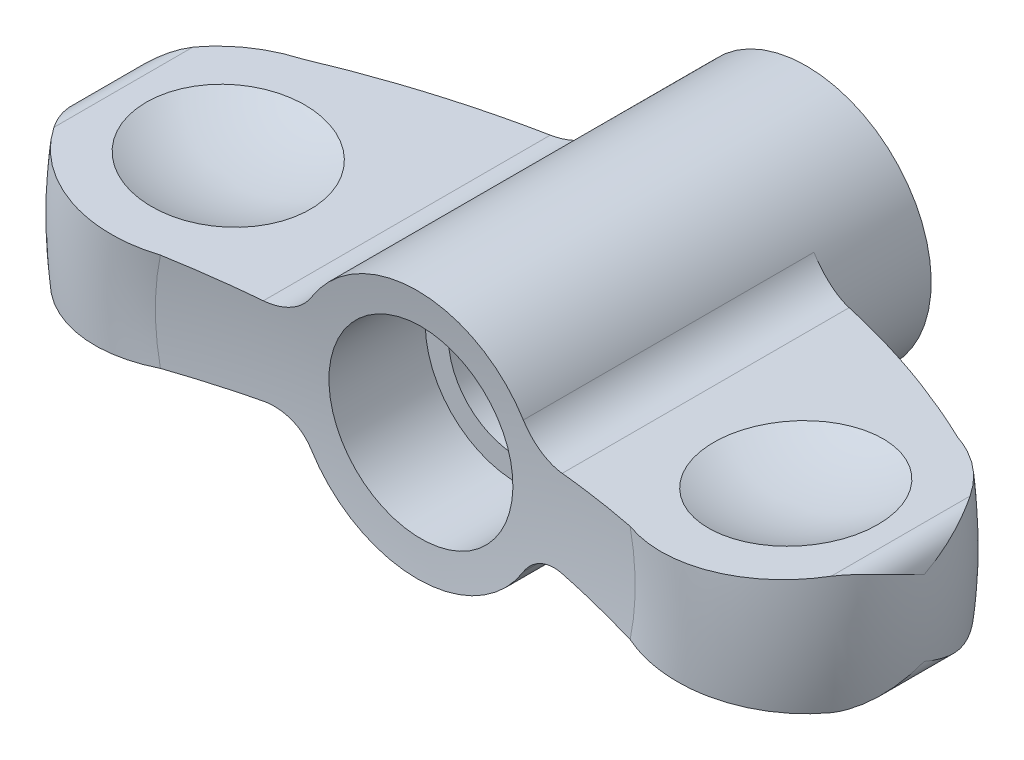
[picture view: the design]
ISO-10303-21;
HEADER;
FILE_DESCRIPTION(('STEP AP214'),'2;1');
FILE_NAME('part.step','',(''),(''),'','','');
FILE_SCHEMA(('AUTOMOTIVE_DESIGN { 1 0 10303 214 1 1 1 1 }'));
ENDSEC;
DATA;
#1=APPLICATION_CONTEXT('core data for automotive mechanical design processes');
#2=APPLICATION_PROTOCOL_DEFINITION('international standard','automotive_design',2000,#1);
#3=PRODUCT_CONTEXT('',#1,'mechanical');
#4=PRODUCT('Part','Part','',(#3));
#5=PRODUCT_RELATED_PRODUCT_CATEGORY('part','',(#4));
#6=PRODUCT_DEFINITION_FORMATION('','',#4);
#7=PRODUCT_DEFINITION_CONTEXT('part definition',#1,'design');
#8=PRODUCT_DEFINITION('design','',#6,#7);
#9=PRODUCT_DEFINITION_SHAPE('','',#8);
#10=(LENGTH_UNIT() NAMED_UNIT(*) SI_UNIT(.MILLI.,.METRE.));
#11=(NAMED_UNIT(*) PLANE_ANGLE_UNIT() SI_UNIT($,.RADIAN.));
#12=(NAMED_UNIT(*) SI_UNIT($,.STERADIAN.) SOLID_ANGLE_UNIT());
#13=UNCERTAINTY_MEASURE_WITH_UNIT(LENGTH_MEASURE(1.E-05),#10,'distance_accuracy_value','');
#14=(GEOMETRIC_REPRESENTATION_CONTEXT(3) GLOBAL_UNCERTAINTY_ASSIGNED_CONTEXT((#13)) GLOBAL_UNIT_ASSIGNED_CONTEXT((#10,
#11,#12)) REPRESENTATION_CONTEXT('',''));
#15=CARTESIAN_POINT('',(0.,0.,0.));
#16=DIRECTION('',(0.,0.,1.));
#17=DIRECTION('',(1.,0.,0.));
#18=AXIS2_PLACEMENT_3D('',#15,#16,#17);
#19=CARTESIAN_POINT('',(0.,0.,22.4));
#20=DIRECTION('',(0.,0.,1.));
#21=DIRECTION('',(-1.09310760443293E-09,1.,0.));
#22=AXIS2_PLACEMENT_3D('',#19,#20,#21);
#23=TOROIDAL_SURFACE('',#22,21.8999999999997,9.6);
#24=CARTESIAN_POINT('',(-18.1474454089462,-3.75149992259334,13.4105144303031));
#25=CARTESIAN_POINT('',(-17.8905850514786,-3.73467864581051,13.5060281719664));
#26=CARTESIAN_POINT('',(-17.637760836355,-3.71812168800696,13.6124268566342));
#27=CARTESIAN_POINT('',(-17.1419285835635,-3.68565061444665,13.8461211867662));
#28=CARTESIAN_POINT('',(-16.8989202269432,-3.66973647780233,13.9734161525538));
#29=CARTESIAN_POINT('',(-16.424509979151,-3.63866828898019,14.2479997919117));
#30=CARTESIAN_POINT('',(-16.1931050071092,-3.62351403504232,14.3952831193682));
#31=CARTESIAN_POINT('',(-15.7434802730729,-3.59406900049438,14.7088327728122));
#32=CARTESIAN_POINT('',(-15.5252603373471,-3.579778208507,14.8750988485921));
#33=CARTESIAN_POINT('',(-15.1034606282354,-3.55215537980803,15.2255617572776));
#34=CARTESIAN_POINT('',(-14.8998888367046,-3.53882386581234,15.409768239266));
#35=CARTESIAN_POINT('',(-14.5090032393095,-3.51322554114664,15.7947666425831));
#36=CARTESIAN_POINT('',(-14.3216896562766,-3.50095874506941,15.995558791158));
#37=CARTESIAN_POINT('',(-13.964772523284,-3.47758494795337,16.4122828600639));
#38=CARTESIAN_POINT('',(-13.7951642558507,-3.46647763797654,16.6282107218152));
#39=CARTESIAN_POINT('',(-13.4749045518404,-3.44550446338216,17.0737519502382));
#40=CARTESIAN_POINT('',(-13.3242529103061,-3.43563858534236,17.3033651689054));
#41=CARTESIAN_POINT('',(-13.0439598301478,-3.41728274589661,17.7732237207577));
#42=CARTESIAN_POINT('',(-12.9141954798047,-3.40878473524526,18.0133954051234));
#43=CARTESIAN_POINT('',(-12.6756273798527,-3.39316138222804,18.5039680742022));
#44=CARTESIAN_POINT('',(-12.5668227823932,-3.3860359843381,18.754368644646));
#45=CARTESIAN_POINT('',(-12.3710778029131,-3.37321703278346,19.2636307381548));
#46=CARTESIAN_POINT('',(-12.284138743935,-3.36752356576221,19.5224927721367));
#47=CARTESIAN_POINT('',(-12.1328924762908,-3.35761874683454,20.0467739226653));
#48=CARTESIAN_POINT('',(-12.06858489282,-3.35340737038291,20.3121929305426));
#49=CARTESIAN_POINT('',(-11.9641647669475,-3.34656910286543,20.8426066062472));
#50=CARTESIAN_POINT('',(-11.9236219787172,-3.34391403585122,21.1075162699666));
#51=CARTESIAN_POINT('',(-11.8652424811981,-3.34009087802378,21.639835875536));
#52=CARTESIAN_POINT('',(-11.8474054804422,-3.33892276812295,21.9072457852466));
#53=CARTESIAN_POINT('',(-11.8345982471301,-3.33808404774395,22.4425774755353));
#54=CARTESIAN_POINT('',(-11.8396248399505,-3.33841322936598,22.7104991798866));
#55=CARTESIAN_POINT('',(-11.8724923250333,-3.34056565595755,23.2449323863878));
#56=CARTESIAN_POINT('',(-11.9003330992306,-3.34238889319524,23.5114438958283));
#57=CARTESIAN_POINT('',(-11.9780680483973,-3.34747960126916,24.0376567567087));
#58=CARTESIAN_POINT('',(-12.027669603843,-3.35072790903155,24.2974015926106));
#59=CARTESIAN_POINT('',(-12.1484267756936,-3.35863605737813,24.8118052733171));
#60=CARTESIAN_POINT('',(-12.2195821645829,-3.36329588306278,25.0664641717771));
#61=CARTESIAN_POINT('',(-12.382844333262,-3.37398759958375,25.5689078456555));
#62=CARTESIAN_POINT('',(-12.4749485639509,-3.38001932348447,25.8166934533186));
#63=CARTESIAN_POINT('',(-12.6794078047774,-3.3934089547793,26.3038316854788));
#64=CARTESIAN_POINT('',(-12.7917703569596,-3.40076735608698,26.5431811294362));
#65=CARTESIAN_POINT('',(-13.0369078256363,-3.41682092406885,27.0137884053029));
#66=CARTESIAN_POINT('',(-13.1698514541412,-3.42552713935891,27.2449579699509));
#67=CARTESIAN_POINT('',(-13.4544154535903,-3.44416267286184,27.69545672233));
#68=CARTESIAN_POINT('',(-13.6060365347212,-3.45409203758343,27.914785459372));
#69=CARTESIAN_POINT('',(-13.9268367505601,-3.47510060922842,28.3401572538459));
#70=CARTESIAN_POINT('',(-14.0960166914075,-3.4861798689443,28.5461997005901));
#71=CARTESIAN_POINT('',(-14.4507138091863,-3.50940828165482,28.9436423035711));
#72=CARTESIAN_POINT('',(-14.6362312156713,-3.52155744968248,29.1350422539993));
#73=CARTESIAN_POINT('',(-15.0260268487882,-3.54708439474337,29.5054914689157));
#74=CARTESIAN_POINT('',(-15.2305978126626,-3.56048134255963,29.6842314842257));
#75=CARTESIAN_POINT('',(-15.6538967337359,-3.58820235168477,30.0239900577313));
#76=CARTESIAN_POINT('',(-15.8726245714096,-3.60252640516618,30.1850087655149));
#77=CARTESIAN_POINT('',(-16.3227525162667,-3.6320043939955,30.4882695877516));
#78=CARTESIAN_POINT('',(-16.5541555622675,-3.64715852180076,30.6305073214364));
#79=CARTESIAN_POINT('',(-17.0278914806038,-3.67818255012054,30.8951425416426));
#80=CARTESIAN_POINT('',(-17.2702206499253,-3.69405220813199,31.017546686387));
#81=CARTESIAN_POINT('',(-17.7669669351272,-3.72658313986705,31.2429802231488));
#82=CARTESIAN_POINT('',(-18.0214889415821,-3.74325128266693,31.3457775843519));
#83=CARTESIAN_POINT('',(-18.5382654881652,-3.77709395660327,31.5295393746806));
#84=CARTESIAN_POINT('',(-18.8005200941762,-3.79426849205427,31.6105036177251));
#85=CARTESIAN_POINT('',(-19.3309113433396,-3.82900276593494,31.7500060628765));
#86=CARTESIAN_POINT('',(-19.5990481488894,-3.8465625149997,31.8085436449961));
#87=CARTESIAN_POINT('',(-20.1392890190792,-3.88194182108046,31.9027453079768));
#88=CARTESIAN_POINT('',(-20.411393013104,-3.899761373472,31.9384097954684));
#89=CARTESIAN_POINT('',(-20.9576381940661,-3.93553388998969,31.9865808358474));
#90=CARTESIAN_POINT('',(-21.2317794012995,-3.95348685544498,31.9990871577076));
#91=CARTESIAN_POINT('',(-21.7801364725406,-3.98939767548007,32.0008164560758));
#92=CARTESIAN_POINT('',(-22.0543523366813,-4.00735553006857,31.9900393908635));
#93=CARTESIAN_POINT('',(-22.6008596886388,-4.04314521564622,31.9452447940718));
#94=CARTESIAN_POINT('',(-22.8731513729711,-4.06097705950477,31.9112296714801));
#95=CARTESIAN_POINT('',(-23.4138724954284,-4.09638781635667,31.8201695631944));
#96=CARTESIAN_POINT('',(-23.6823019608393,-4.11396673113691,31.7631247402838));
#97=CARTESIAN_POINT('',(-24.2118784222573,-4.14864764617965,31.6267614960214));
#98=CARTESIAN_POINT('',(-24.4730575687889,-4.16575175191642,31.5475684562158));
#99=CARTESIAN_POINT('',(-24.9877954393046,-4.19946091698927,31.3673123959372));
#100=CARTESIAN_POINT('',(-25.2413540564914,-4.21606596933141,31.2662490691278));
#101=CARTESIAN_POINT('',(-25.7391278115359,-4.2486641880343,31.0428965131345));
#102=CARTESIAN_POINT('',(-25.983338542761,-4.26465706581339,30.9205974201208));
#103=CARTESIAN_POINT('',(-26.4605066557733,-4.29590586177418,30.6556646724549));
#104=CARTESIAN_POINT('',(-26.6934645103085,-4.31116181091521,30.5130318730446));
#105=CARTESIAN_POINT('',(-27.1452633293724,-4.34074922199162,30.2092249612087));
#106=CARTESIAN_POINT('',(-27.3641711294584,-4.35508506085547,30.0481506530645));
#107=CARTESIAN_POINT('',(-27.7875858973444,-4.38281365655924,29.708008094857));
#108=CARTESIAN_POINT('',(-27.9920934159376,-4.39620644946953,29.5289405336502));
#109=CARTESIAN_POINT('',(-28.3848624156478,-4.42192811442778,29.1544313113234));
#110=CARTESIAN_POINT('',(-28.5731528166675,-4.43425888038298,28.9590200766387));
#111=CARTESIAN_POINT('',(-28.9324617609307,-4.45778931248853,28.5530043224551));
#112=CARTESIAN_POINT('',(-29.1034908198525,-4.46898966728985,28.3424091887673));
#113=CARTESIAN_POINT('',(-29.3193740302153,-4.48312743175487,28.0522910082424));
#114=CARTESIAN_POINT('',(-29.3724491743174,-4.48660321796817,27.978811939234));
#115=CARTESIAN_POINT('',(-29.476441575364,-4.49341347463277,27.8304567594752));
#116=CARTESIAN_POINT('',(-29.5273611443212,-4.49674809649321,27.7555822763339));
#117=CARTESIAN_POINT('',(-29.5772181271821,-4.50001313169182,27.6799919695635));
#118=B_SPLINE_CURVE_WITH_KNOTS('',3,(#24,#25,#26,#27,#28,#29,#30,#31,#32,#33,#34,#35,#36,#37,
#38,#39,#40,#41,#42,#43,#44,#45,#46,#47,#48,#49,#50,#51,#52,#53,#54,#55,#56,#57,#58,#59,#60,#61,
#62,#63,#64,#65,#66,#67,#68,#69,#70,#71,#72,#73,#74,#75,#76,#77,#78,#79,#80,#81,#82,#83,#84,#85,
#86,#87,#88,#89,#90,#91,#92,#93,#94,#95,#96,#97,#98,#99,#100,#101,#102,#103,#104,#105,#106,#107,
#108,#109,#110,#111,#112,#113,#114,#115,#116,#117),.UNSPECIFIED.,.F.,.F.,(4,2,2,2,2,2,2,2,2,2,2,
2,2,2,2,2,2,2,2,2,2,2,2,2,2,2,2,2,2,2,2,2,2,2,2,2,2,2,2,2,2,2,2,2,2,2,4),(0.,0.823429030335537,
1.64683128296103,2.47001373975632,3.29318534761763,4.11680216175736,4.94043026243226,
5.76383834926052,6.5872375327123,7.40559872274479,8.22392680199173,9.04230438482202,
9.8606684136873,10.6637182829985,11.4667578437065,12.2696859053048,13.0726098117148,
13.8650526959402,14.6574872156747,15.449825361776,16.2424591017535,17.0419728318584,
17.8415169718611,18.6410978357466,19.4406899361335,20.2556974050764,21.070697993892,
21.8858883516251,22.7008044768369,23.5248358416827,24.3488742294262,25.1729353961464,
25.9969819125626,26.8210366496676,27.6450928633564,28.4690636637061,29.2930286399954,
30.1124203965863,30.9318236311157,31.7516084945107,32.5713588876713,33.3868657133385,
34.2023413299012,35.0163312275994,35.8298222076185,36.1019244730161,36.3737270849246),.UNSPECIFIED.);
#119=CARTESIAN_POINT('',(-17.8721248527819,-3.73346972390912,31.2823000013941));
#120=VERTEX_POINT('',#119);
#121=CARTESIAN_POINT('',(-29.5770181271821,-4.50000003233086,27.6802951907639));
#122=VERTEX_POINT('',#121);
#123=EDGE_CURVE('E175',#120,#122,#118,.T.);
#124=ORIENTED_EDGE('',*,*,#123,.F.);
#125=CARTESIAN_POINT('',(0.,0.,31.2823000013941));
#126=DIRECTION('',(0.,0.,1.));
#127=DIRECTION('',(-1.09310760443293E-09,1.,0.));
#128=AXIS2_PLACEMENT_3D('',#125,#126,#127);
#129=CIRCLE('',#128,18.2579200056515);
#130=CARTESIAN_POINT('',(-17.8721248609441,3.7334696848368,31.2823000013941));
#131=VERTEX_POINT('',#130);
#132=EDGE_CURVE('E187',#131,#120,#129,.T.);
#133=ORIENTED_EDGE('',*,*,#132,.F.);
#134=CARTESIAN_POINT('',(-29.5772181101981,4.50001306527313,27.6799920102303));
#135=CARTESIAN_POINT('',(-29.4283813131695,4.49026603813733,27.9057071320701));
#136=CARTESIAN_POINT('',(-29.2699701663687,4.47989200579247,28.125073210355));
#137=CARTESIAN_POINT('',(-28.9352574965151,4.4579723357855,28.5496181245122));
#138=CARTESIAN_POINT('',(-28.7589571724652,4.44642677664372,28.7547979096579));
#139=CARTESIAN_POINT('',(-28.3898682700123,4.42225587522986,29.1493363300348));
#140=CARTESIAN_POINT('',(-28.1970944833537,4.40963150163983,29.3387088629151));
#141=CARTESIAN_POINT('',(-27.7963194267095,4.38338553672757,29.700509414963));
#142=CARTESIAN_POINT('',(-27.5883182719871,4.36976395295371,29.8729375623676));
#143=CARTESIAN_POINT('',(-27.1584989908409,4.3416159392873,30.1997036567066));
#144=CARTESIAN_POINT('',(-26.9366758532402,4.32708918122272,30.3540349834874));
#145=CARTESIAN_POINT('',(-26.4808650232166,4.29723903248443,30.6434656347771));
#146=CARTESIAN_POINT('',(-26.2468771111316,4.28191562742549,30.7785646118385));
#147=CARTESIAN_POINT('',(-25.7684462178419,4.25058413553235,31.0285776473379));
#148=CARTESIAN_POINT('',(-25.5240048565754,4.23457615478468,31.1434948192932));
#149=CARTESIAN_POINT('',(-25.0263706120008,4.20198707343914,31.3523874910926));
#150=CARTESIAN_POINT('',(-24.7731777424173,4.18540597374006,31.446363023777));
#151=CARTESIAN_POINT('',(-24.2590478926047,4.1517366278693,31.612996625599));
#152=CARTESIAN_POINT('',(-23.9980896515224,4.13464698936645,31.6855888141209));
#153=CARTESIAN_POINT('',(-23.4709078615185,4.10012289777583,31.8086173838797));
#154=CARTESIAN_POINT('',(-23.2046821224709,4.08268830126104,31.8590443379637));
#155=CARTESIAN_POINT('',(-22.6689091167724,4.04760158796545,31.9373839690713));
#156=CARTESIAN_POINT('',(-22.399361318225,4.02994943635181,31.9652929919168));
#157=CARTESIAN_POINT('',(-21.858996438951,3.99456201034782,31.9984159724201));
#158=CARTESIAN_POINT('',(-21.5881799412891,3.97682677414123,32.003639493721));
#159=CARTESIAN_POINT('',(-21.0454404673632,3.94128384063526,31.9913795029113));
#160=CARTESIAN_POINT('',(-20.7735205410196,3.92347634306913,31.9737602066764));
#161=CARTESIAN_POINT('',(-20.232112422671,3.88802059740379,31.9157373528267));
#162=CARTESIAN_POINT('',(-19.9626242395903,3.87037234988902,31.8753337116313));
#163=CARTESIAN_POINT('',(-19.4280257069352,3.83536255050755,31.7720671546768));
#164=CARTESIAN_POINT('',(-19.1629144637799,3.81800094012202,31.7092088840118));
#165=CARTESIAN_POINT('',(-18.6387730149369,3.78367595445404,31.5614710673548));
#166=CARTESIAN_POINT('',(-18.3797450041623,3.76671272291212,31.4765837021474));
#167=CARTESIAN_POINT('',(-17.8682212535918,3.73321404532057,31.2848646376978));
#168=CARTESIAN_POINT('',(-17.6157711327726,3.7166815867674,31.1779106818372));
#169=CARTESIAN_POINT('',(-17.1207308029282,3.68426237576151,30.9431230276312));
#170=CARTESIAN_POINT('',(-16.878140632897,3.66837562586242,30.815289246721));
#171=CARTESIAN_POINT('',(-16.404527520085,3.63735964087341,30.5396362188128));
#172=CARTESIAN_POINT('',(-16.1735051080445,3.62223044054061,30.3918160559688));
#173=CARTESIAN_POINT('',(-15.7246795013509,3.59283774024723,30.0772205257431));
#174=CARTESIAN_POINT('',(-15.5068766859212,3.57857426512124,29.9104446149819));
#175=CARTESIAN_POINT('',(-15.0856203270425,3.55098702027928,29.5587225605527));
#176=CARTESIAN_POINT('',(-14.8821981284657,3.53766530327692,29.3737387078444));
#177=CARTESIAN_POINT('',(-14.4917116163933,3.51209311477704,28.9871837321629));
#178=CARTESIAN_POINT('',(-14.3046468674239,3.49984261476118,28.7856130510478));
#179=CARTESIAN_POINT('',(-13.948272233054,3.47650434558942,28.367276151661));
#180=CARTESIAN_POINT('',(-13.7789624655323,3.46541658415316,28.1505098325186));
#181=CARTESIAN_POINT('',(-13.4594078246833,3.44448958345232,27.7032976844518));
#182=CARTESIAN_POINT('',(-13.3091626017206,3.43465032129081,27.4728521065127));
#183=CARTESIAN_POINT('',(-13.0300075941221,3.41636901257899,27.0017206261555));
#184=CARTESIAN_POINT('',(-12.9009427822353,3.40791681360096,26.7611269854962));
#185=CARTESIAN_POINT('',(-12.6638563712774,3.39239049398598,26.2698561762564));
#186=CARTESIAN_POINT('',(-12.55582645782,3.38531582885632,26.0191830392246));
#187=CARTESIAN_POINT('',(-12.3616487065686,3.37259951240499,25.5094385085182));
#188=CARTESIAN_POINT('',(-12.2755026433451,3.36695797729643,25.2503664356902));
#189=CARTESIAN_POINT('',(-12.1258566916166,3.35715796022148,24.7257346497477));
#190=CARTESIAN_POINT('',(-12.0623564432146,3.35299945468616,24.4601750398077));
#191=CARTESIAN_POINT('',(-11.9595441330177,3.34626648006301,23.9295575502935));
#192=CARTESIAN_POINT('',(-11.9198013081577,3.34366380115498,23.6645834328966));
#193=CARTESIAN_POINT('',(-11.8630211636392,3.33994538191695,23.1322038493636));
#194=CARTESIAN_POINT('',(-11.8459835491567,3.33882962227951,22.8647984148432));
#195=CARTESIAN_POINT('',(-11.8347668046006,3.33809505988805,22.3295252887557));
#196=CARTESIAN_POINT('',(-11.8405861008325,3.33847615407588,22.0616576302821));
#197=CARTESIAN_POINT('',(-11.875027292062,3.34073163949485,21.5273997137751));
#198=CARTESIAN_POINT('',(-11.9036490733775,3.34260602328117,21.2610094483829));
#199=CARTESIAN_POINT('',(-11.9829240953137,3.3477975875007,20.7350583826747));
#200=CARTESIAN_POINT('',(-12.0332886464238,3.35109586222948,20.475453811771));
#201=CARTESIAN_POINT('',(-12.1555550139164,3.35910284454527,19.9613934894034));
#202=CARTESIAN_POINT('',(-12.2274566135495,3.36381153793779,19.7069376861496));
#203=CARTESIAN_POINT('',(-12.3921774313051,3.37459877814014,19.2049950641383));
#204=CARTESIAN_POINT('',(-12.4849912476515,3.38067697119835,18.9575064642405));
#205=CARTESIAN_POINT('',(-12.6908448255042,3.39415791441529,18.4709993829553));
#206=CARTESIAN_POINT('',(-12.8038936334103,3.40156125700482,18.2319847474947));
#207=CARTESIAN_POINT('',(-13.0503991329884,3.41770441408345,17.7620583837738));
#208=CARTESIAN_POINT('',(-13.1840279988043,3.42645550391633,17.5312373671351));
#209=CARTESIAN_POINT('',(-13.4698675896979,3.44517457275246,17.0815911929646));
#210=CARTESIAN_POINT('',(-13.6220707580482,3.4551420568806,16.8627612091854));
#211=CARTESIAN_POINT('',(-13.9440945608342,3.47623075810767,16.4382825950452));
#212=CARTESIAN_POINT('',(-14.1139279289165,3.48735280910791,16.2326436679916));
#213=CARTESIAN_POINT('',(-14.4698944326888,3.51066435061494,15.8360721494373));
#214=CARTESIAN_POINT('',(-14.6560271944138,3.52285381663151,15.6451392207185));
#215=CARTESIAN_POINT('',(-15.0471805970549,3.54846967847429,15.2755429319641));
#216=CARTESIAN_POINT('',(-15.2525053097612,3.56191598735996,15.0972026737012));
#217=CARTESIAN_POINT('',(-15.6772923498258,3.58973444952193,14.7583242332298));
#218=CARTESIAN_POINT('',(-15.8967545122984,3.60410659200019,14.5977858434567));
#219=CARTESIAN_POINT('',(-16.3478939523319,3.63365082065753,14.2958496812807));
#220=CARTESIAN_POINT('',(-16.5795509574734,3.648821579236,14.1544214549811));
#221=CARTESIAN_POINT('',(-17.0537037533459,3.67987290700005,13.8914238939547));
#222=CARTESIAN_POINT('',(-17.2961933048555,3.69575306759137,13.7698433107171));
#223=CARTESIAN_POINT('',(-17.6425873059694,3.71843772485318,13.6138611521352));
#224=CARTESIAN_POINT('',(-17.74267739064,3.7249924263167,13.5707938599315));
#225=CARTESIAN_POINT('',(-17.9441132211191,3.73818406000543,13.4880908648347));
#226=CARTESIAN_POINT('',(-18.0454572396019,3.74482087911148,13.4484509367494));
#227=CARTESIAN_POINT('',(-18.1474454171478,3.75149988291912,13.4105144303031));
#228=B_SPLINE_CURVE_WITH_KNOTS('',3,(#134,#135,#136,#137,#138,#139,#140,#141,#142,#143,#144,
#145,#146,#147,#148,#149,#150,#151,#152,#153,#154,#155,#156,#157,#158,#159,#160,#161,#162,#163,
#164,#165,#166,#167,#168,#169,#170,#171,#172,#173,#174,#175,#176,#177,#178,#179,#180,#181,#182,
#183,#184,#185,#186,#187,#188,#189,#190,#191,#192,#193,#194,#195,#196,#197,#198,#199,#200,#201,
#202,#203,#204,#205,#206,#207,#208,#209,#210,#211,#212,#213,#214,#215,#216,#217,#218,#219,#220,
#221,#222,#223,#224,#225,#226,#227),.UNSPECIFIED.,.F.,.F.,(4,2,2,2,2,2,2,2,2,2,2,2,2,2,2,2,2,2,
2,2,2,2,2,2,2,2,2,2,2,2,2,2,2,2,2,2,2,2,2,2,2,2,2,2,2,2,4),(0.,0.81138385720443,
1.62271336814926,2.43332187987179,3.24392425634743,4.05482224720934,4.86573488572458,
5.6765223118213,6.48730846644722,7.30056707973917,8.11417124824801,8.92790742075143,
9.74130050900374,10.5595508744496,11.3778042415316,12.1958884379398,13.0142634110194,
13.8373004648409,14.6603407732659,15.4834188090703,16.3065204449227,17.131364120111,
17.9561858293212,18.7810130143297,19.6058250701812,20.4243011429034,21.242453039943,
22.0606712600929,22.8788764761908,23.6817568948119,24.484626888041,25.2874416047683,
26.0902523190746,26.8827166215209,27.6751729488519,28.4674248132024,29.2600317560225,
30.0596712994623,30.8589865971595,31.6588832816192,32.458761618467,33.2746912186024,
34.0906113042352,34.905215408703,35.7193562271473,36.0467859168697,36.3738060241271),.UNSPECIFIED.);
#229=CARTESIAN_POINT('',(-29.577018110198,4.49999996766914,27.6802952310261));
#230=VERTEX_POINT('',#229);
#231=EDGE_CURVE('E289',#230,#131,#228,.T.);
#232=ORIENTED_EDGE('',*,*,#231,.F.);
#233=CARTESIAN_POINT('',(-31.3695646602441,2.86363632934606,22.4));
#234=CARTESIAN_POINT('',(-31.3693228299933,2.86628555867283,22.4059654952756));
#235=CARTESIAN_POINT('',(-31.3690751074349,2.86893434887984,22.4119311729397));
#236=CARTESIAN_POINT('',(-31.3455550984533,3.11453940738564,22.9652019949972));
#237=CARTESIAN_POINT('',(-31.2727100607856,3.35362318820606,23.5139845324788));
#238=CARTESIAN_POINT('',(-31.0906514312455,3.68216337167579,24.3317563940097));
#239=CARTESIAN_POINT('',(-31.0177760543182,3.78670942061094,24.6035877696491));
#240=CARTESIAN_POINT('',(-30.8477677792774,3.98135438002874,25.1449637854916));
#241=CARTESIAN_POINT('',(-30.7506472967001,4.07146064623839,25.4145095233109));
#242=CARTESIAN_POINT('',(-30.5719332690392,4.20252897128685,25.8529322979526));
#243=CARTESIAN_POINT('',(-30.4974342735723,4.24947679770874,26.0229493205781));
#244=CARTESIAN_POINT('',(-30.3388744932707,4.33328279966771,26.3608778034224));
#245=CARTESIAN_POINT('',(-30.2548212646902,4.37014887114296,26.5287908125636));
#246=CARTESIAN_POINT('',(-30.0769796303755,4.43174326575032,26.8627513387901));
#247=CARTESIAN_POINT('',(-29.9831491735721,4.45641629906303,27.0287870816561));
#248=CARTESIAN_POINT('',(-29.8357178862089,4.48201224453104,27.2752518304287));
#249=CARTESIAN_POINT('',(-29.7853951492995,4.48864303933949,27.3570723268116));
#250=CARTESIAN_POINT('',(-29.6826484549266,4.49763621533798,27.5196657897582));
#251=CARTESIAN_POINT('',(-29.630223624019,4.49999680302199,27.6004383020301));
#252=CARTESIAN_POINT('',(-29.5768181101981,4.49999995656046,27.6805954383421));
#253=B_SPLINE_CURVE_WITH_KNOTS('',3,(#233,#234,#235,#236,#237,#238,#239,#240,#241,#242,#243,
#244,#245,#246,#247,#248,#249,#250,#251,#252),.UNSPECIFIED.,.F.,.F.,(4,2,2,2,2,2,2,2,2,4),(0.,
0.0195959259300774,1.81731826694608,2.71712331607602,3.61646853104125,4.19044381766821,
4.76396827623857,5.34007007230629,5.62881792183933,5.9176870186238),.UNSPECIFIED.);
#254=CARTESIAN_POINT('',(-31.3695646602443,2.86363632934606,22.4));
#255=VERTEX_POINT('',#254);
#256=EDGE_CURVE('E346',#255,#230,#253,.T.);
#257=ORIENTED_EDGE('',*,*,#256,.F.);
#258=CARTESIAN_POINT('',(-29.576818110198,4.49999995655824,17.119404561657));
#259=CARTESIAN_POINT('',(-29.6191393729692,4.50000099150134,17.1829266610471));
#260=CARTESIAN_POINT('',(-29.6608485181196,4.4985171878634,17.2468391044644));
#261=CARTESIAN_POINT('',(-29.7429683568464,4.49280696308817,17.3753522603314));
#262=CARTESIAN_POINT('',(-29.7833793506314,4.48858118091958,17.4399528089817));
#263=CARTESIAN_POINT('',(-29.9024609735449,4.47214702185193,17.6344933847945));
#264=CARTESIAN_POINT('',(-29.9791105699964,4.4561804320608,17.7653678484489));
#265=CARTESIAN_POINT('',(-30.1263186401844,4.41582921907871,18.0284830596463));
#266=CARTESIAN_POINT('',(-30.1969002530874,4.39147852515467,18.1607162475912));
#267=CARTESIAN_POINT('',(-30.3321494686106,4.33558285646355,18.426742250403));
#268=CARTESIAN_POINT('',(-30.3968138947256,4.30403404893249,18.5605358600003));
#269=CARTESIAN_POINT('',(-30.5626786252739,4.21088532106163,18.9222641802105));
#270=CARTESIAN_POINT('',(-30.658240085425,4.14358637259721,19.1513508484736));
#271=CARTESIAN_POINT('',(-30.8316829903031,3.99568948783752,19.6118454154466));
#272=CARTESIAN_POINT('',(-30.9095558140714,3.91508509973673,19.8432543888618));
#273=CARTESIAN_POINT('',(-31.1166837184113,3.6580671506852,20.5407057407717));
#274=CARTESIAN_POINT('',(-31.2192514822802,3.46657221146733,21.0095421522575));
#275=CARTESIAN_POINT('',(-31.3069727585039,3.20184753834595,21.6292554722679));
#276=CARTESIAN_POINT('',(-31.3245600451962,3.13661932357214,21.7798368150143));
#277=CARTESIAN_POINT('',(-31.3522803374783,3.00489987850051,22.080989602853));
#278=CARTESIAN_POINT('',(-31.3624220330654,2.93841021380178,22.2315608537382));
#279=CARTESIAN_POINT('',(-31.3690750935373,2.86893441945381,22.3880686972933));
#280=CARTESIAN_POINT('',(-31.3693228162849,2.86628562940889,22.3940343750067));
#281=CARTESIAN_POINT('',(-31.3695646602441,2.86363632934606,22.4));
#282=B_SPLINE_CURVE_WITH_KNOTS('',3,(#258,#259,#260,#261,#262,#263,#264,#265,#266,#267,#268,
#269,#270,#271,#272,#273,#274,#275,#276,#277,#278,#279,#280,#281),.UNSPECIFIED.,.F.,.F.,(4,2,2,
2,2,2,2,2,2,2,2,4),(0.,0.228945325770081,0.457837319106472,0.914918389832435,1.37017104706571,
1.8256666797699,2.59598824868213,3.36668444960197,4.90952775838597,5.40460012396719,
5.89909375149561,5.91868967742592),.UNSPECIFIED.);
#283=CARTESIAN_POINT('',(-29.577018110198,4.49999996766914,17.1197047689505));
#284=VERTEX_POINT('',#283);
#285=EDGE_CURVE('E339',#284,#255,#282,.T.);
#286=ORIENTED_EDGE('',*,*,#285,.F.);
#287=CARTESIAN_POINT('',(-24.9182172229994,4.19490432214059,13.4105144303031));
#288=CARTESIAN_POINT('',(-25.174728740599,4.21170275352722,13.506320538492));
#289=CARTESIAN_POINT('',(-25.4271515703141,4.22823342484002,13.6131252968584));
#290=CARTESIAN_POINT('',(-25.9220334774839,4.26064226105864,13.8478633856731));
#291=CARTESIAN_POINT('',(-26.1644920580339,4.27652039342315,13.9757977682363));
#292=CARTESIAN_POINT('',(-26.6315223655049,4.30710528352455,14.2483504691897));
#293=CARTESIAN_POINT('',(-26.8563943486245,4.32183170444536,14.3924524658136));
#294=CARTESIAN_POINT('',(-27.2933789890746,4.35044896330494,14.6988790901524));
#295=CARTESIAN_POINT('',(-27.5054935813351,4.36433992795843,14.8612009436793));
#296=CARTESIAN_POINT('',(-27.888316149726,4.38941021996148,15.1803070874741));
#297=CARTESIAN_POINT('',(-28.0607864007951,4.40070495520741,15.3349749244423));
#298=CARTESIAN_POINT('',(-28.3941147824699,4.42253397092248,15.656391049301));
#299=CARTESIAN_POINT('',(-28.5549737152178,4.43306830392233,15.8231385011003));
#300=CARTESIAN_POINT('',(-28.8677866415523,4.45355380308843,16.1718241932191));
#301=CARTESIAN_POINT('',(-29.0194509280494,4.463485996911,16.3540235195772));
#302=CARTESIAN_POINT('',(-29.3089338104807,4.4824436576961,16.7291933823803));
#303=CARTESIAN_POINT('',(-29.4467504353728,4.49146899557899,16.9221654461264));
#304=CARTESIAN_POINT('',(-29.577218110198,4.50001306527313,17.1200079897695));
#305=B_SPLINE_CURVE_WITH_KNOTS('',3,(#287,#288,#289,#290,#291,#292,#293,#294,#295,#296,#297,
#298,#299,#300,#301,#302,#303,#304),.UNSPECIFIED.,.F.,.F.,(4,2,2,2,2,2,2,2,4),(0.,
0.822759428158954,1.64555983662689,2.44710662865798,3.24853154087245,3.94375872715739,
4.6389378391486,5.35009750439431,6.06135825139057),.UNSPECIFIED.);
#306=CARTESIAN_POINT('',(-24.9187524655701,4.19493937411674,13.4107144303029));
#307=VERTEX_POINT('',#306);
#308=EDGE_CURVE('E280',#307,#284,#305,.T.);
#309=ORIENTED_EDGE('',*,*,#308,.F.);
#310=CARTESIAN_POINT('',(0.,0.,13.4107144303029));
#311=DIRECTION('',(0.,0.,1.));
#312=DIRECTION('',(-1.09310760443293E-09,1.,0.));
#313=AXIS2_PLACEMENT_3D('',#310,#311,#312);
#314=CIRCLE('',#313,25.2693834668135);
#315=CARTESIAN_POINT('',(-24.918752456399,-4.1949394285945,13.4107144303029));
#316=VERTEX_POINT('',#315);
#317=EDGE_CURVE('E183',#307,#316,#314,.T.);
#318=ORIENTED_EDGE('',*,*,#317,.T.);
#319=CARTESIAN_POINT('',(-29.5772181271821,-4.50001313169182,17.1200080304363));
#320=CARTESIAN_POINT('',(-29.4265102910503,-4.49014357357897,16.8914517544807));
#321=CARTESIAN_POINT('',(-29.2659808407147,-4.47963081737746,16.6694035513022));
#322=CARTESIAN_POINT('',(-28.9265816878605,-4.45740423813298,16.2398574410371));
#323=CARTESIAN_POINT('',(-28.7477118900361,-4.44569040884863,16.032359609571));
#324=CARTESIAN_POINT('',(-28.3777669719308,-4.42146344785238,15.6385922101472));
#325=CARTESIAN_POINT('',(-28.1871253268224,-4.40897870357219,15.4519133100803));
#326=CARTESIAN_POINT('',(-27.7910307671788,-4.38303925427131,15.0951091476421));
#327=CARTESIAN_POINT('',(-27.5855799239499,-4.36958468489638,14.92498157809));
#328=CARTESIAN_POINT('',(-27.1888740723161,-4.3436052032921,14.6233879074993));
#329=CARTESIAN_POINT('',(-26.9992422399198,-4.33118658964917,14.4897704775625));
#330=CARTESIAN_POINT('',(-26.6108443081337,-4.305751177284,14.2366062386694));
#331=CARTESIAN_POINT('',(-26.4120783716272,-4.29273438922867,14.1170591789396));
#332=CARTESIAN_POINT('',(-26.0017910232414,-4.26586548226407,13.8900697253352));
#333=CARTESIAN_POINT('',(-25.7900813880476,-4.25200103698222,13.7829689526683));
#334=CARTESIAN_POINT('',(-25.3593416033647,-4.22379274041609,13.5846713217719));
#335=CARTESIAN_POINT('',(-25.1403106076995,-4.20944883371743,13.4934763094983));
#336=CARTESIAN_POINT('',(-24.9182172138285,-4.19490437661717,13.4105144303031));
#337=B_SPLINE_CURVE_WITH_KNOTS('',3,(#319,#320,#321,#322,#323,#324,#325,#326,#327,#328,#329,
#330,#331,#332,#333,#334,#335,#336),.UNSPECIFIED.,.F.,.F.,(4,2,2,2,2,2,2,2,4),(0.,
0.821594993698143,1.64319425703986,2.44361485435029,3.24392371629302,3.94026356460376,
4.63659100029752,5.34893291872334,6.06135745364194),.UNSPECIFIED.);
#338=CARTESIAN_POINT('',(-29.5770181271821,-4.50000003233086,17.1197048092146));
#339=VERTEX_POINT('',#338);
#340=EDGE_CURVE('E297',#339,#316,#337,.T.);
#341=ORIENTED_EDGE('',*,*,#340,.F.);
#342=CARTESIAN_POINT('',(-31.3695646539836,-2.86363639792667,22.4));
#343=CARTESIAN_POINT('',(-31.3693228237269,-2.86628562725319,22.3940345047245));
#344=CARTESIAN_POINT('',(-31.3690751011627,-2.86893441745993,22.3880688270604));
#345=CARTESIAN_POINT('',(-31.3455550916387,-3.11453947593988,21.8347980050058));
#346=CARTESIAN_POINT('',(-31.2727100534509,-3.35362325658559,21.2860154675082));
#347=CARTESIAN_POINT('',(-31.0906514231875,-3.6821634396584,20.4682436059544));
#348=CARTESIAN_POINT('',(-31.0177760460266,-3.7867094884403,20.1964122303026));
#349=CARTESIAN_POINT('',(-30.8477677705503,-3.98135444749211,19.6550362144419));
#350=CARTESIAN_POINT('',(-30.7506472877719,-4.07146071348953,19.3854904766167));
#351=CARTESIAN_POINT('',(-30.57193326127,-4.20252903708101,18.9470677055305));
#352=CARTESIAN_POINT('',(-30.4974342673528,-4.24947686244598,18.7770506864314));
#353=CARTESIAN_POINT('',(-30.3388744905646,-4.33328286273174,18.4391222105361));
#354=CARTESIAN_POINT('',(-30.2548212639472,-4.37014893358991,18.2712092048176));
#355=CARTESIAN_POINT('',(-30.0769796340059,-4.43174332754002,17.9372486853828));
#356=CARTESIAN_POINT('',(-29.9831491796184,-4.45641636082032,17.7712129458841));
#357=CARTESIAN_POINT('',(-29.8357178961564,-4.48201230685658,17.5247482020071));
#358=CARTESIAN_POINT('',(-29.7853951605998,-4.48864310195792,17.4429277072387));
#359=CARTESIAN_POINT('',(-29.6826484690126,-4.49763627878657,17.2803342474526));
#360=CARTESIAN_POINT('',(-29.6302236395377,-4.49999686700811,17.1995617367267));
#361=CARTESIAN_POINT('',(-29.5768181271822,-4.50000002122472,17.1194046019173));
#362=B_SPLINE_CURVE_WITH_KNOTS('',3,(#342,#343,#344,#345,#346,#347,#348,#349,#350,#351,#352,
#353,#354,#355,#356,#357,#358,#359,#360,#361),.UNSPECIFIED.,.F.,.F.,(4,2,2,2,2,2,2,2,2,4),(0.,
0.0195959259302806,1.81731826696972,2.7171233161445,3.61646853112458,4.19044380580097,
4.7639682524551,5.34007003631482,5.62881787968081,5.91768697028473),.UNSPECIFIED.);
#363=CARTESIAN_POINT('',(-31.3695646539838,-2.86363639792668,22.4));
#364=VERTEX_POINT('',#363);
#365=EDGE_CURVE('E9',#364,#339,#362,.T.);
#366=ORIENTED_EDGE('',*,*,#365,.F.);
#367=CARTESIAN_POINT('',(-29.5768181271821,-4.50000002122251,27.6805953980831));
#368=CARTESIAN_POINT('',(-29.6191393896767,-4.50000105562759,27.6170732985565));
#369=CARTESIAN_POINT('',(-29.6608485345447,-4.49851725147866,27.553160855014));
#370=CARTESIAN_POINT('',(-29.7429683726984,-4.49280702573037,27.4246476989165));
#371=CARTESIAN_POINT('',(-29.7833793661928,-4.48858124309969,27.3600471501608));
#372=CARTESIAN_POINT('',(-29.9024609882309,-4.47214708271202,27.1655065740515));
#373=CARTESIAN_POINT('',(-29.9791105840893,-4.45618049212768,27.0346321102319));
#374=CARTESIAN_POINT('',(-30.1263186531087,-4.41582927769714,26.7715168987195));
#375=CARTESIAN_POINT('',(-30.1969002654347,-4.3914785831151,26.6392837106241));
#376=CARTESIAN_POINT('',(-30.332149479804,-4.3355829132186,26.3732577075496));
#377=CARTESIAN_POINT('',(-30.3968139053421,-4.3040341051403,26.2394640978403));
#378=CARTESIAN_POINT('',(-30.5626786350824,-4.21088537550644,25.8777357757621));
#379=CARTESIAN_POINT('',(-30.6582400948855,-4.14358642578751,25.6486491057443));
#380=CARTESIAN_POINT('',(-30.8316829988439,-3.99568953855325,25.1881545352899));
#381=CARTESIAN_POINT('',(-30.90955582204,-3.9150851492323,24.9567455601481));
#382=CARTESIAN_POINT('',(-31.1166837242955,-3.65806719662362,24.2592942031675));
#383=CARTESIAN_POINT('',(-31.2192514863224,-3.46657225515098,23.7904577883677));
#384=CARTESIAN_POINT('',(-31.3069727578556,-3.2018475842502,23.1707444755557));
#385=CARTESIAN_POINT('',(-31.324560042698,-3.13661937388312,23.0201631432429));
#386=CARTESIAN_POINT('',(-31.3522803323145,-3.00489993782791,22.7190103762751));
#387=CARTESIAN_POINT('',(-31.3624220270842,-2.93841027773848,22.5684391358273));
#388=CARTESIAN_POINT('',(-31.3690750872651,-2.86893448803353,22.4119313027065));
#389=CARTESIAN_POINT('',(-31.3693228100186,-2.86628569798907,22.4059656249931));
#390=CARTESIAN_POINT('',(-31.3695646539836,-2.86363639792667,22.4));
#391=B_SPLINE_CURVE_WITH_KNOTS('',3,(#367,#368,#369,#370,#371,#372,#373,#374,#375,#376,#377,
#378,#379,#380,#381,#382,#383,#384,#385,#386,#387,#388,#389,#390),.UNSPECIFIED.,.F.,.F.,(4,2,2,
2,2,2,2,2,2,2,2,4),(0.,0.228945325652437,0.45783731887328,0.914918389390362,1.37017104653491,
1.82566667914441,2.59598825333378,3.36668445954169,4.9095277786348,5.40460010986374,
5.89909370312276,5.91868962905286),.UNSPECIFIED.);
#392=EDGE_CURVE('E28',#122,#364,#391,.T.);
#393=ORIENTED_EDGE('',*,*,#392,.F.);
#394=EDGE_LOOP('',(#124,#133,#232,#257,#286,#309,#318,#341,#366,#393));
#395=FACE_BOUND('',#394,.T.);
#396=ADVANCED_FACE('F14',(#395),#23,.T.);
#397=CARTESIAN_POINT('',(0.,0.,76.6132216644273));
#398=DIRECTION('',(0.,0.,1.));
#399=DIRECTION('',(-1.09310760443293E-09,1.,0.));
#400=AXIS2_PLACEMENT_3D('',#397,#398,#399);
#401=DEGENERATE_TOROIDAL_SURFACE('',#400,7.41274216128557,71.1525000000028,.F.);
#402=CARTESIAN_POINT('',(0.,0.,7.5));
#403=DIRECTION('',(0.,0.,1.));
#404=DIRECTION('',(-1.09310760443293E-09,1.,0.));
#405=AXIS2_PLACEMENT_3D('',#402,#403,#404);
#406=CIRCLE('',#405,9.5);
#407=CARTESIAN_POINT('',(8.07537707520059,-5.00382704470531,7.5));
#408=VERTEX_POINT('',#407);
#409=CARTESIAN_POINT('',(8.07537710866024,5.00382699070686,7.5));
#410=VERTEX_POINT('',#409);
#411=EDGE_CURVE('E162',#408,#410,#406,.T.);
#412=ORIENTED_EDGE('',*,*,#411,.T.);
#413=CARTESIAN_POINT('',(8.07525318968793,5.00402699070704,7.50000000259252));
#414=CARTESIAN_POINT('',(8.12665454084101,4.92103774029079,7.4999917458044));
#415=CARTESIAN_POINT('',(8.1814486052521,4.84015820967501,7.5013354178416));
#416=CARTESIAN_POINT('',(8.29736182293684,4.68318006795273,7.50668034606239));
#417=CARTESIAN_POINT('',(8.35847989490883,4.60708064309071,7.51068114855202));
#418=CARTESIAN_POINT('',(8.48644181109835,4.46037529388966,7.52128110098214));
#419=CARTESIAN_POINT('',(8.5532712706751,4.38975637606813,7.52787386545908));
#420=CARTESIAN_POINT('',(8.69224302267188,4.25429557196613,7.54356393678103));
#421=CARTESIAN_POINT('',(8.76438537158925,4.18945374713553,7.55266127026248));
#422=CARTESIAN_POINT('',(8.98795756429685,4.00427130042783,7.5835471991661));
#423=CARTESIAN_POINT('',(9.14667405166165,3.8931121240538,7.60894168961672));
#424=CARTESIAN_POINT('',(9.47864044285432,3.69815735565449,7.66816076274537));
#425=CARTESIAN_POINT('',(9.65189888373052,3.61437798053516,7.70199032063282));
#426=CARTESIAN_POINT('',(10.0125625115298,3.47403572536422,7.77763329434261));
#427=CARTESIAN_POINT('',(10.2002113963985,3.41819607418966,7.81962324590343));
#428=CARTESIAN_POINT('',(10.5805892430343,3.3377434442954,7.90948197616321));
#429=CARTESIAN_POINT('',(10.773313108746,3.31310027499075,7.95734502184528));
#430=CARTESIAN_POINT('',(11.0336535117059,3.30081514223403,8.02491673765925));
#431=CARTESIAN_POINT('',(11.1013248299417,3.2995405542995,8.0427473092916));
#432=CARTESIAN_POINT('',(11.2363731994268,3.30079633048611,8.07885369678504));
#433=CARTESIAN_POINT('',(11.3037505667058,3.30331933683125,8.09712858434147));
#434=CARTESIAN_POINT('',(11.370972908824,3.30772214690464,8.11561851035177));
#435=B_SPLINE_CURVE_WITH_KNOTS('',3,(#413,#414,#415,#416,#417,#418,#419,#420,#421,#422,#423,
#424,#425,#426,#427,#428,#429,#430,#431,#432,#433,#434),.UNSPECIFIED.,.F.,.F.,(4,2,2,2,2,2,2,2,
2,2,4),(0.,0.292752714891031,0.585455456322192,0.877441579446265,1.16943080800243,
1.75277206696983,2.33645821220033,2.93455895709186,3.53208044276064,3.74198071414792,
3.95147483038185),.UNSPECIFIED.);
#436=CARTESIAN_POINT('',(11.370772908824,3.30770904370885,8.1155634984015));
#437=VERTEX_POINT('',#436);
#438=EDGE_CURVE('E151',#410,#437,#435,.T.);
#439=ORIENTED_EDGE('',*,*,#438,.T.);
#440=CARTESIAN_POINT('',(24.9191403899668,4.19496483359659,13.4109144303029));
#441=CARTESIAN_POINT('',(23.8381391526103,4.12417220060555,12.8535823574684));
#442=CARTESIAN_POINT('',(22.7428134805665,4.05244148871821,12.3242059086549));
#443=CARTESIAN_POINT('',(20.5293345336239,3.90748513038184,11.3241128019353));
#444=CARTESIAN_POINT('',(19.4112500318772,3.8342639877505,10.8532432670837));
#445=CARTESIAN_POINT('',(17.1522467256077,3.68632632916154,9.96991193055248));
#446=CARTESIAN_POINT('',(16.0113274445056,3.61160978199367,9.55745134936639));
#447=CARTESIAN_POINT('',(14.2836536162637,3.49846784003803,8.98318373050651));
#448=CARTESIAN_POINT('',(13.7042390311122,3.46052312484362,8.79894257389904));
#449=CARTESIAN_POINT('',(12.5407906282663,3.38433119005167,8.44572577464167));
#450=CARTESIAN_POINT('',(11.9567567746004,3.34608396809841,8.27675025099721));
#451=CARTESIAN_POINT('',(11.370572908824,3.30769594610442,8.115508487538));
#452=B_SPLINE_CURVE_WITH_KNOTS('',3,(#440,#441,#442,#443,#444,#445,#446,#447,#448,#449,#450,
#451),.UNSPECIFIED.,.F.,.F.,(4,2,2,2,2,4),(0.,3.65437061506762,7.29898215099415,
10.9436698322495,12.7710429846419,14.5984303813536),.UNSPECIFIED.);
#453=CARTESIAN_POINT('',(24.918752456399,4.1949394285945,13.4107144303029));
#454=VERTEX_POINT('',#453);
#455=EDGE_CURVE('E210',#454,#437,#452,.T.);
#456=ORIENTED_EDGE('',*,*,#455,.F.);
#457=CARTESIAN_POINT('',(24.9187524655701,-4.19493937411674,13.4107144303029));
#458=VERTEX_POINT('',#457);
#459=EDGE_CURVE('E182',#458,#454,#314,.T.);
#460=ORIENTED_EDGE('',*,*,#459,.F.);
#461=CARTESIAN_POINT('',(11.3705729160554,-3.3076959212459,8.11550848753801));
#462=CARTESIAN_POINT('',(13.3194357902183,-3.43532309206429,8.65165350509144));
#463=CARTESIAN_POINT('',(15.2454387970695,-3.56145321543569,9.27335320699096));
#464=CARTESIAN_POINT('',(19.0285581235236,-3.80920220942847,10.6774595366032));
#465=CARTESIAN_POINT('',(20.8859409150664,-3.93083853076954,11.4591449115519));
#466=CARTESIAN_POINT('',(23.0778618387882,-4.07438309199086,12.4939591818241));
#467=CARTESIAN_POINT('',(23.4481408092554,-4.09863192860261,12.6727423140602));
#468=CARTESIAN_POINT('',(24.1858660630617,-4.14694409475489,13.0369148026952));
#469=CARTESIAN_POINT('',(24.5533094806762,-4.17100723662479,13.2223099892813));
#470=CARTESIAN_POINT('',(24.9191403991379,-4.19496477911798,13.4109144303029));
#471=B_SPLINE_CURVE_WITH_KNOTS('',3,(#461,#462,#463,#464,#465,#466,#467,#468,#469,#470),
.UNSPECIFIED.,.F.,.F.,(4,2,2,2,4),(0.,6.07517314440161,12.1235385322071,13.3591937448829,
14.5959668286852),.UNSPECIFIED.);
#472=CARTESIAN_POINT('',(11.3707729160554,-3.3077090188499,8.11556349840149));
#473=VERTEX_POINT('',#472);
#474=EDGE_CURVE('E202',#473,#458,#471,.T.);
#475=ORIENTED_EDGE('',*,*,#474,.F.);
#476=CARTESIAN_POINT('',(11.3709729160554,-3.30772212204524,8.11561851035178));
#477=CARTESIAN_POINT('',(11.2701325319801,-3.30110508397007,8.08788118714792));
#478=CARTESIAN_POINT('',(11.1688817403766,-3.29874080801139,8.06061250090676));
#479=CARTESIAN_POINT('',(10.9662236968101,-3.30257078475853,8.00721735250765));
#480=CARTESIAN_POINT('',(10.8648164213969,-3.30876647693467,7.98109108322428));
#481=CARTESIAN_POINT('',(10.6624409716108,-3.32978236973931,7.93016922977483));
#482=CARTESIAN_POINT('',(10.5614733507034,-3.344611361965,7.90537503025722));
#483=CARTESIAN_POINT('',(10.3608328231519,-3.38287017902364,7.85737208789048));
#484=CARTESIAN_POINT('',(10.2611598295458,-3.40629942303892,7.83416323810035));
#485=CARTESIAN_POINT('',(9.96486870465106,-3.48949810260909,7.76717843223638));
#486=CARTESIAN_POINT('',(9.77109378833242,-3.56216661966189,7.72607333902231));
#487=CARTESIAN_POINT('',(9.39755023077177,-3.74054377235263,7.65286990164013));
#488=CARTESIAN_POINT('',(9.21777675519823,-3.8462409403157,7.62076843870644));
#489=CARTESIAN_POINT('',(8.96611053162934,-4.02532516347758,7.58103605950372));
#490=CARTESIAN_POINT('',(8.886463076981,-4.08719629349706,7.56933067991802));
#491=CARTESIAN_POINT('',(8.73245596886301,-4.21758209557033,7.54853793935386));
#492=CARTESIAN_POINT('',(8.65809406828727,-4.28609391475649,7.53944946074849));
#493=CARTESIAN_POINT('',(8.51538278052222,-4.42916783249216,7.52402786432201));
#494=CARTESIAN_POINT('',(8.44702397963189,-4.50372009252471,7.5176903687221));
#495=CARTESIAN_POINT('',(8.31677244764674,-4.65839173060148,7.50784180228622));
#496=CARTESIAN_POINT('',(8.25487550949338,-4.73850742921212,7.5043288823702));
#497=CARTESIAN_POINT('',(8.17532777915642,-4.85096451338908,7.50150027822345));
#498=CARTESIAN_POINT('',(8.15464683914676,-4.88116884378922,7.50093670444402));
#499=CARTESIAN_POINT('',(8.11423882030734,-4.94215927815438,7.5001864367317));
#500=CARTESIAN_POINT('',(8.09451058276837,-4.97294460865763,7.49999927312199));
#501=CARTESIAN_POINT('',(8.07525315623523,-5.0040270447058,7.50000000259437));
#502=B_SPLINE_CURVE_WITH_KNOTS('',3,(#476,#477,#478,#479,#480,#481,#482,#483,#484,#485,#486,
#487,#488,#489,#490,#491,#492,#493,#494,#495,#496,#497,#498,#499,#500,#501),.UNSPECIFIED.,.F.,
.F.,(4,2,2,2,2,2,2,2,2,2,2,2,4),(0.,0.314298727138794,0.628650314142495,0.943322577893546,
1.25797359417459,1.88762970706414,2.51706744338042,2.82134305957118,3.12548853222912,
3.42914821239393,3.73260894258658,3.84242577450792,3.95210549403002),.UNSPECIFIED.);
#503=EDGE_CURVE('E152',#473,#408,#502,.T.);
#504=ORIENTED_EDGE('',*,*,#503,.T.);
#505=EDGE_LOOP('',(#412,#439,#456,#460,#475,#504));
#506=FACE_BOUND('',#505,.T.);
#507=ADVANCED_FACE('F437',(#506),#401,.F.);
#508=CARTESIAN_POINT('',(-9.5,-1.03845216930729E-08,0.));
#509=DIRECTION('',(0.,0.,-1.));
#510=DIRECTION('',(1.09310760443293E-09,-1.,0.));
#511=AXIS2_PLACEMENT_3D('',#508,#509,#510);
#512=PLANE('',#511);
#513=CARTESIAN_POINT('',(0.,0.,0.));
#514=DIRECTION('',(0.,0.,-1.));
#515=DIRECTION('',(1.09310760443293E-09,-1.,0.));
#516=AXIS2_PLACEMENT_3D('',#513,#514,#515);
#517=CIRCLE('',#516,5.);
#518=CARTESIAN_POINT('',(5.46553802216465E-09,-5.,0.));
#519=VERTEX_POINT('',#518);
#520=EDGE_CURVE('E567',#519,#519,#517,.T.);
#521=ORIENTED_EDGE('',*,*,#520,.F.);
#522=EDGE_LOOP('',(#521));
#523=FACE_BOUND('',#522,.T.);
#524=CARTESIAN_POINT('',(0.,0.,0.));
#525=DIRECTION('',(0.,0.,1.));
#526=DIRECTION('',(-1.09310760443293E-09,1.,0.));
#527=AXIS2_PLACEMENT_3D('',#524,#525,#526);
#528=CIRCLE('',#527,9.5);
#529=CARTESIAN_POINT('',(-1.03845222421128E-08,9.5,0.));
#530=VERTEX_POINT('',#529);
#531=EDGE_CURVE('E170',#530,#530,#528,.T.);
#532=ORIENTED_EDGE('',*,*,#531,.F.);
#533=EDGE_LOOP('',(#532));
#534=FACE_BOUND('',#533,.T.);
#535=ADVANCED_FACE('F16',(#523,#534),#512,.T.);
#536=CARTESIAN_POINT('',(-5.,-5.46553796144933E-09,20.));
#537=DIRECTION('',(0.,0.,1.));
#538=DIRECTION('',(-1.09310760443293E-09,1.,0.));
#539=AXIS2_PLACEMENT_3D('',#536,#537,#538);
#540=PLANE('',#539);
#541=CARTESIAN_POINT('',(0.,0.,20.));
#542=DIRECTION('',(0.,0.,1.));
#543=DIRECTION('',(-1.09310760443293E-09,1.,0.));
#544=AXIS2_PLACEMENT_3D('',#541,#542,#543);
#545=CIRCLE('',#544,5.25);
#546=CARTESIAN_POINT('',(-5.73881492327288E-09,5.25,20.));
#547=VERTEX_POINT('',#546);
#548=EDGE_CURVE('E199',#547,#547,#545,.T.);
#549=ORIENTED_EDGE('',*,*,#548,.T.);
#550=EDGE_LOOP('',(#549));
#551=FACE_BOUND('',#550,.T.);
#552=CARTESIAN_POINT('',(0.,0.,20.));
#553=DIRECTION('',(0.,0.,1.));
#554=DIRECTION('',(-1.09310760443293E-09,1.,0.));
#555=AXIS2_PLACEMENT_3D('',#552,#553,#554);
#556=CIRCLE('',#555,5.);
#557=CARTESIAN_POINT('',(-5.46553802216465E-09,5.,20.));
#558=VERTEX_POINT('',#557);
#559=EDGE_CURVE('E564',#558,#558,#556,.T.);
#560=ORIENTED_EDGE('',*,*,#559,.F.);
#561=EDGE_LOOP('',(#560));
#562=FACE_BOUND('',#561,.T.);
#563=ADVANCED_FACE('F503',(#551,#562),#540,.T.);
#564=CARTESIAN_POINT('',(0.,0.,29.));
#565=DIRECTION('',(0.,0.,1.));
#566=DIRECTION('',(-1.09310760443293E-09,1.,0.));
#567=AXIS2_PLACEMENT_3D('',#564,#565,#566);
#568=CYLINDRICAL_SURFACE('',#567,5.25);
#569=CARTESIAN_POINT('',(0.,0.,22.));
#570=DIRECTION('',(0.,0.,1.));
#571=DIRECTION('',(-1.09310760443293E-09,1.,0.));
#572=AXIS2_PLACEMENT_3D('',#569,#570,#571);
#573=CIRCLE('',#572,5.25);
#574=CARTESIAN_POINT('',(-5.73881492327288E-09,5.25,22.));
#575=VERTEX_POINT('',#574);
#576=EDGE_CURVE('E196',#575,#575,#573,.T.);
#577=ORIENTED_EDGE('',*,*,#576,.T.);
#578=EDGE_LOOP('',(#577));
#579=FACE_BOUND('',#578,.T.);
#580=ORIENTED_EDGE('',*,*,#548,.F.);
#581=EDGE_LOOP('',(#580));
#582=FACE_BOUND('',#581,.T.);
#583=ADVANCED_FACE('F726',(#579,#582),#568,.F.);
#584=CARTESIAN_POINT('',(-5.25,-5.73881475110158E-09,22.));
#585=DIRECTION('',(0.,0.,1.));
#586=DIRECTION('',(-1.09310760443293E-09,1.,0.));
#587=AXIS2_PLACEMENT_3D('',#584,#585,#586);
#588=PLANE('',#587);
#589=CARTESIAN_POINT('',(0.,0.,22.));
#590=DIRECTION('',(0.,0.,1.));
#591=DIRECTION('',(-1.09310760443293E-09,1.,0.));
#592=AXIS2_PLACEMENT_3D('',#589,#590,#591);
#593=CIRCLE('',#592,7.);
#594=CARTESIAN_POINT('',(-7.65175323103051E-09,7.,22.));
#595=VERTEX_POINT('',#594);
#596=EDGE_CURVE('E193',#595,#595,#593,.T.);
#597=ORIENTED_EDGE('',*,*,#596,.T.);
#598=EDGE_LOOP('',(#597));
#599=FACE_BOUND('',#598,.T.);
#600=ORIENTED_EDGE('',*,*,#576,.F.);
#601=EDGE_LOOP('',(#600));
#602=FACE_BOUND('',#601,.T.);
#603=ADVANCED_FACE('F718',(#599,#602),#588,.T.);
#604=CARTESIAN_POINT('',(0.,0.,29.));
#605=DIRECTION('',(0.,0.,1.));
#606=DIRECTION('',(-1.09310760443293E-09,1.,0.));
#607=AXIS2_PLACEMENT_3D('',#604,#605,#606);
#608=CYLINDRICAL_SURFACE('',#607,7.);
#609=CARTESIAN_POINT('',(0.,0.,29.3310570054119));
#610=DIRECTION('',(0.,0.,1.));
#611=DIRECTION('',(-1.09310760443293E-09,1.,0.));
#612=AXIS2_PLACEMENT_3D('',#609,#610,#611);
#613=CIRCLE('',#612,7.);
#614=CARTESIAN_POINT('',(-7.65175323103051E-09,7.,29.3310570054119));
#615=VERTEX_POINT('',#614);
#616=EDGE_CURVE('E190',#615,#615,#613,.T.);
#617=ORIENTED_EDGE('',*,*,#616,.T.);
#618=EDGE_LOOP('',(#617));
#619=FACE_BOUND('',#618,.T.);
#620=ORIENTED_EDGE('',*,*,#596,.F.);
#621=EDGE_LOOP('',(#620));
#622=FACE_BOUND('',#621,.T.);
#623=ADVANCED_FACE('F710',(#619,#622),#608,.F.);
#624=CARTESIAN_POINT('',(2.25514051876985E-13,0.,103.170910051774));
#625=DIRECTION('',(0.,0.,1.));
#626=DIRECTION('',(-1.,-1.09310760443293E-09,0.));
#627=AXIS2_PLACEMENT_3D('',#624,#625,#626);
#628=SPHERICAL_SURFACE('',#627,74.1709100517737);
#629=ORIENTED_EDGE('',*,*,#616,.F.);
#630=EDGE_LOOP('',(#629));
#631=FACE_BOUND('',#630,.T.);
#632=CARTESIAN_POINT('',(-11.3709729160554,3.30772212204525,29.9514874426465));
#633=CARTESIAN_POINT('',(-11.2702305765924,3.30110869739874,29.9355428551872));
#634=CARTESIAN_POINT('',(-11.1691518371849,3.29874969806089,29.9199533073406));
#635=CARTESIAN_POINT('',(-10.967028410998,3.30254167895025,29.8895902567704));
#636=CARTESIAN_POINT('',(-10.8659837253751,3.30869292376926,29.874816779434));
#637=CARTESIAN_POINT('',(-10.6646868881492,3.3295022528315,29.8461992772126));
#638=CARTESIAN_POINT('',(-10.5644344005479,3.34415650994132,29.8323548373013));
#639=CARTESIAN_POINT('',(-10.3653936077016,3.38189476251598,29.8056884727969));
#640=CARTESIAN_POINT('',(-10.2666052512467,3.4049784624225,29.7928665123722));
#641=CARTESIAN_POINT('',(-10.0711417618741,3.45946198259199,29.7683312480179));
#642=CARTESIAN_POINT('',(-9.97446794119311,3.49086681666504,29.7566186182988));
#643=CARTESIAN_POINT('',(-9.78396783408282,3.56180490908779,29.7343941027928));
#644=CARTESIAN_POINT('',(-9.69014255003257,3.60134099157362,29.7238826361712));
#645=CARTESIAN_POINT('',(-9.50607021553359,3.6882773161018,29.7041448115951));
#646=CARTESIAN_POINT('',(-9.41582307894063,3.73567736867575,29.6949184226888));
#647=CARTESIAN_POINT('',(-9.23957915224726,3.83802260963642,29.677821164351));
#648=CARTESIAN_POINT('',(-9.15358229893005,3.89296768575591,29.669950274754));
#649=CARTESIAN_POINT('',(-8.9873343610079,4.00942692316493,29.6556976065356));
#650=CARTESIAN_POINT('',(-8.90703380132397,4.07086871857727,29.6493015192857));
#651=CARTESIAN_POINT('',(-8.75185429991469,4.20032102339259,29.6379481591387));
#652=CARTESIAN_POINT('',(-8.67697332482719,4.26832904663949,29.632990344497));
#653=CARTESIAN_POINT('',(-8.53326106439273,4.41034713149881,29.6245545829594));
#654=CARTESIAN_POINT('',(-8.46442144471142,4.48434864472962,29.6210745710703));
#655=CARTESIAN_POINT('',(-8.33321278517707,4.63787779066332,29.6156128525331));
#656=CARTESIAN_POINT('',(-8.27083994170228,4.71740212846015,29.6136302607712));
#657=CARTESIAN_POINT('',(-8.18797692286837,4.8327266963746,29.6119039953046));
#658=CARTESIAN_POINT('',(-8.16459591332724,4.86647137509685,29.6115298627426));
#659=CARTESIAN_POINT('',(-8.11903115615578,4.93469615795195,29.6110318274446));
#660=CARTESIAN_POINT('',(-8.09684584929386,4.96917521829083,29.6109075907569));
#661=CARTESIAN_POINT('',(-8.07525306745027,5.00402718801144,29.6109080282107));
#662=B_SPLINE_CURVE_WITH_KNOTS('',3,(#632,#633,#634,#635,#636,#637,#638,#639,#640,#641,#642,
#643,#644,#645,#646,#647,#648,#649,#650,#651,#652,#653,#654,#655,#656,#657,#658,#659,#660,#661),
.UNSPECIFIED.,.F.,.F.,(4,2,2,2,2,2,2,2,2,2,2,2,2,2,4),(0.,0.306544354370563,0.613098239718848,
0.919514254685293,1.2259195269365,1.53250984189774,1.83920682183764,2.14589641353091,
2.45258144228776,2.75615245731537,3.0596089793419,3.36264006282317,3.66549188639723,
3.788637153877,3.91161774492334),.UNSPECIFIED.);
#663=CARTESIAN_POINT('',(-11.3707729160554,3.3077090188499,29.9514557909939));
#664=VERTEX_POINT('',#663);
#665=CARTESIAN_POINT('',(-8.07537698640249,5.00382718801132,29.6109080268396));
#666=VERTEX_POINT('',#665);
#667=EDGE_CURVE('E527',#664,#666,#662,.T.);
#668=ORIENTED_EDGE('',*,*,#667,.F.);
#669=CARTESIAN_POINT('',(0.167132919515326,2.55211441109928,103.170910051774));
#670=DIRECTION('',(-0.0653480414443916,-0.997862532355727,0.));
#671=DIRECTION('',(0.997862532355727,-0.0653480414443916,0.));
#672=AXIS2_PLACEMENT_3D('',#669,#670,#671);
#673=CIRCLE('',#672,74.1268013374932);
#674=EDGE_CURVE('E419',#664,#131,#673,.F.);
#675=ORIENTED_EDGE('',*,*,#674,.T.);
#676=ORIENTED_EDGE('',*,*,#132,.T.);
#677=CARTESIAN_POINT('',(0.167132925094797,-2.55211441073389,103.170910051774));
#678=DIRECTION('',(-0.0653480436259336,0.997862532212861,0.));
#679=DIRECTION('',(-0.997862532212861,-0.0653480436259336,0.));
#680=AXIS2_PLACEMENT_3D('',#677,#678,#679);
#681=CIRCLE('',#680,74.1268013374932);
#682=CARTESIAN_POINT('',(-11.370772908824,-3.30770904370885,29.951455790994));
#683=VERTEX_POINT('',#682);
#684=EDGE_CURVE('E171',#120,#683,#681,.F.);
#685=ORIENTED_EDGE('',*,*,#684,.T.);
#686=CARTESIAN_POINT('',(-8.07525307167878,-5.00402718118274,29.6109080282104));
#687=CARTESIAN_POINT('',(-8.1279773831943,-4.91890610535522,29.6109050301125));
#688=CARTESIAN_POINT('',(-8.18426788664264,-4.83600039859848,29.6116495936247));
#689=CARTESIAN_POINT('',(-8.30353556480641,-4.67518470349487,29.6146197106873));
#690=CARTESIAN_POINT('',(-8.36651222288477,-4.59727432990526,29.6168451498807));
#691=CARTESIAN_POINT('',(-8.49861978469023,-4.44710893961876,29.6227586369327));
#692=CARTESIAN_POINT('',(-8.56774171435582,-4.37484595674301,29.6264445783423));
#693=CARTESIAN_POINT('',(-8.71168118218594,-4.23637135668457,29.6352474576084));
#694=CARTESIAN_POINT('',(-8.78649866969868,-4.1701596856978,29.64036438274));
#695=CARTESIAN_POINT('',(-9.0187510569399,-3.98127784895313,29.6578137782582));
#696=CARTESIAN_POINT('',(-9.18407289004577,-3.86826220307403,29.6722487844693));
#697=CARTESIAN_POINT('',(-9.53070421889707,-3.67133522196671,29.7062861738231));
#698=CARTESIAN_POINT('',(-9.71201988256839,-3.58743517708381,29.725890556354));
#699=CARTESIAN_POINT('',(-10.0868745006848,-3.4503081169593,29.7698552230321));
#700=CARTESIAN_POINT('',(-10.2804937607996,-3.39731194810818,29.7942495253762));
#701=CARTESIAN_POINT('',(-10.673145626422,-3.32426624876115,29.8469878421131));
#702=CARTESIAN_POINT('',(-10.8721695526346,-3.30416674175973,29.8753257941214));
#703=CARTESIAN_POINT('',(-11.1210683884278,-3.29969229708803,29.9127340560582));
#704=CARTESIAN_POINT('',(-11.1711558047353,-3.29984127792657,29.9203619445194));
#705=CARTESIAN_POINT('',(-11.2711743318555,-3.30222485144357,29.9357928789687));
#706=CARTESIAN_POINT('',(-11.3211055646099,-3.30445620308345,29.9435956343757));
#707=CARTESIAN_POINT('',(-11.370972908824,-3.30772214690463,29.9514874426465));
#708=B_SPLINE_CURVE_WITH_KNOTS('',3,(#686,#687,#688,#689,#690,#691,#692,#693,#694,#695,#696,
#697,#698,#699,#700,#701,#702,#703,#704,#705,#706,#707),.UNSPECIFIED.,.F.,.F.,(4,2,2,2,2,2,2,2,
2,2,4),(0.,0.300282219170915,0.600541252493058,0.900368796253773,1.20019367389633,
1.79945360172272,2.39894564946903,3.00286025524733,3.60585654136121,3.75782672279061,
3.90956076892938),.UNSPECIFIED.);
#709=CARTESIAN_POINT('',(-8.07537699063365,-5.00382718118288,29.6109080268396));
#710=VERTEX_POINT('',#709);
#711=EDGE_CURVE('E169',#710,#683,#708,.T.);
#712=ORIENTED_EDGE('',*,*,#711,.F.);
#713=CARTESIAN_POINT('',(0.,0.,29.6109080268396));
#714=DIRECTION('',(0.,0.,1.));
#715=DIRECTION('',(-1.09310760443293E-09,1.,0.));
#716=AXIS2_PLACEMENT_3D('',#713,#714,#715);
#717=CIRCLE('',#716,9.5);
#718=CARTESIAN_POINT('',(8.07537707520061,-5.00382704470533,29.6109080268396));
#719=VERTEX_POINT('',#718);
#720=EDGE_CURVE('E158',#710,#719,#717,.T.);
#721=ORIENTED_EDGE('',*,*,#720,.T.);
#722=CARTESIAN_POINT('',(11.3709729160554,-3.30772212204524,29.9514874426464));
#723=CARTESIAN_POINT('',(11.2702305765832,-3.30110869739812,29.9355428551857));
#724=CARTESIAN_POINT('',(11.1691518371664,-3.29874969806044,29.9199533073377));
#725=CARTESIAN_POINT('',(10.9670284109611,-3.3025416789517,29.8895902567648));
#726=CARTESIAN_POINT('',(10.8659837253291,-3.30869292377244,29.8748167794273));
#727=CARTESIAN_POINT('',(10.6646868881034,-3.32950225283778,29.8461992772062));
#728=CARTESIAN_POINT('',(10.5644344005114,-3.34415650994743,29.8323548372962));
#729=CARTESIAN_POINT('',(10.3653936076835,-3.38189476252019,29.8056884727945));
#730=CARTESIAN_POINT('',(10.2666052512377,-3.404978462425,29.792866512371));
#731=CARTESIAN_POINT('',(10.0711417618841,-3.45946198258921,29.7683312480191));
#732=CARTESIAN_POINT('',(9.97446794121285,-3.49086681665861,29.7566186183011));
#733=CARTESIAN_POINT('',(9.78396783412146,-3.56180490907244,29.7343941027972));
#734=CARTESIAN_POINT('',(9.69014255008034,-3.60134099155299,29.7238826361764));
#735=CARTESIAN_POINT('',(9.50607021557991,-3.68827731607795,29.7041448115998));
#736=CARTESIAN_POINT('',(9.4158230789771,-3.73567736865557,29.6949184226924));
#737=CARTESIAN_POINT('',(9.23957915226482,-3.83802260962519,29.6778211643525));
#738=CARTESIAN_POINT('',(9.15358229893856,-3.89296768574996,29.6699502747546));
#739=CARTESIAN_POINT('',(8.98733436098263,-4.00942692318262,29.6556976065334));
#740=CARTESIAN_POINT('',(8.90703380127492,-4.07086871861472,29.6493015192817));
#741=CARTESIAN_POINT('',(8.75185429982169,-4.20032102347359,29.6379481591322));
#742=CARTESIAN_POINT('',(8.67697332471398,-4.26832904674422,29.6329903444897));
#743=CARTESIAN_POINT('',(8.53326106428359,-4.41034713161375,29.6245545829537));
#744=CARTESIAN_POINT('',(8.46442144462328,-4.4843486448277,29.6210745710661));
#745=CARTESIAN_POINT('',(8.33321278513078,-4.63787779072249,29.6156128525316));
#746=CARTESIAN_POINT('',(8.27083994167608,-4.71740212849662,29.6136302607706));
#747=CARTESIAN_POINT('',(8.18797693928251,-4.83272667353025,29.6119039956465));
#748=CARTESIAN_POINT('',(8.1645959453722,-4.86647132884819,29.6115298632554));
#749=CARTESIAN_POINT('',(8.1190312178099,-4.93469606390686,29.6110318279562));
#750=CARTESIAN_POINT('',(8.09684592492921,-4.96917509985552,29.6109075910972));
#751=CARTESIAN_POINT('',(8.07525315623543,-5.00402704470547,29.6109080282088));
#752=B_SPLINE_CURVE_WITH_KNOTS('',3,(#722,#723,#724,#725,#726,#727,#728,#729,#730,#731,#732,
#733,#734,#735,#736,#737,#738,#739,#740,#741,#742,#743,#744,#745,#746,#747,#748,#749,#750,#751),
.UNSPECIFIED.,.F.,.F.,(4,2,2,2,2,2,2,2,2,2,2,2,2,2,4),(0.,0.306544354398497,0.613098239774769,
0.919514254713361,1.2259195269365,1.53250984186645,1.83920682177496,2.1458964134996,
2.45258144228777,2.7561524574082,3.05960897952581,3.36264006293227,3.66549188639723,
3.78863706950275,3.9116175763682),.UNSPECIFIED.);
#753=CARTESIAN_POINT('',(11.3707729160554,-3.3077090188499,29.9514557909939));
#754=VERTEX_POINT('',#753);
#755=EDGE_CURVE('E144',#754,#719,#752,.T.);
#756=ORIENTED_EDGE('',*,*,#755,.F.);
#757=CARTESIAN_POINT('',(-0.167132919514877,-2.55211441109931,103.170910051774));
#758=DIRECTION('',(0.0653480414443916,0.997862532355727,0.));
#759=DIRECTION('',(-0.997862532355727,0.0653480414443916,0.));
#760=AXIS2_PLACEMENT_3D('',#757,#758,#759);
#761=CIRCLE('',#760,74.1268013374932);
#762=CARTESIAN_POINT('',(17.8721248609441,-3.7334696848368,31.2823000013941));
#763=VERTEX_POINT('',#762);
#764=EDGE_CURVE('E427',#754,#763,#761,.F.);
#765=ORIENTED_EDGE('',*,*,#764,.T.);
#766=CARTESIAN_POINT('',(17.8721248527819,3.73346972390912,31.2823000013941));
#767=VERTEX_POINT('',#766);
#768=EDGE_CURVE('E186',#763,#767,#129,.T.);
#769=ORIENTED_EDGE('',*,*,#768,.T.);
#770=CARTESIAN_POINT('',(-0.167132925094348,2.55211441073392,103.170910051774));
#771=DIRECTION('',(0.0653480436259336,-0.997862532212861,0.));
#772=DIRECTION('',(0.997862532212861,0.0653480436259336,0.));
#773=AXIS2_PLACEMENT_3D('',#770,#771,#772);
#774=CIRCLE('',#773,74.1268013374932);
#775=CARTESIAN_POINT('',(11.370772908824,3.30770904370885,29.9514557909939));
#776=VERTEX_POINT('',#775);
#777=EDGE_CURVE('E422',#767,#776,#774,.F.);
#778=ORIENTED_EDGE('',*,*,#777,.T.);
#779=CARTESIAN_POINT('',(8.07525318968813,5.00402699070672,29.6109080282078));
#780=CARTESIAN_POINT('',(8.12797750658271,4.91890591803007,29.6109050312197));
#781=CARTESIAN_POINT('',(8.18426801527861,4.8360002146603,29.6116495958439));
#782=CARTESIAN_POINT('',(8.3035357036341,4.67518452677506,29.6146197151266));
#783=CARTESIAN_POINT('',(8.36651236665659,4.59727415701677,29.6168451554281));
#784=CARTESIAN_POINT('',(8.49861993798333,4.44710877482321,29.6227586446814));
#785=CARTESIAN_POINT('',(8.56774187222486,4.37484579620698,29.6264445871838));
#786=CARTESIAN_POINT('',(8.71168134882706,4.23637120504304,29.635247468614));
#787=CARTESIAN_POINT('',(8.78649884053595,4.17015953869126,29.6403643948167));
#788=CARTESIAN_POINT('',(9.01875123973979,3.98127771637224,29.6578137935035));
#789=CARTESIAN_POINT('',(9.18407308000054,3.86826208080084,29.6722488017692));
#790=CARTESIAN_POINT('',(9.53070442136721,3.67133512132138,29.7062861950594));
#791=CARTESIAN_POINT('',(9.71202009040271,3.58743508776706,29.7258905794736));
#792=CARTESIAN_POINT('',(10.0868747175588,3.45030805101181,29.7698552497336));
#793=CARTESIAN_POINT('',(10.2804939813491,3.39731189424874,29.794249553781));
#794=CARTESIAN_POINT('',(10.6731458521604,3.32426621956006,29.8469878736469));
#795=CARTESIAN_POINT('',(10.8721697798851,3.30416672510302,29.8753258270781));
#796=CARTESIAN_POINT('',(11.1210685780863,3.29969229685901,29.9127340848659));
#797=CARTESIAN_POINT('',(11.17115595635,3.29984127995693,29.9203619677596));
#798=CARTESIAN_POINT('',(11.2711744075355,3.30222485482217,29.9357928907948));
#799=CARTESIAN_POINT('',(11.3211056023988,3.30445620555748,29.9435956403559));
#800=CARTESIAN_POINT('',(11.370972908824,3.30772214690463,29.9514874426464));
#801=B_SPLINE_CURVE_WITH_KNOTS('',3,(#779,#780,#781,#782,#783,#784,#785,#786,#787,#788,#789,
#790,#791,#792,#793,#794,#795,#796,#797,#798,#799,#800),.UNSPECIFIED.,.F.,.F.,(4,2,2,2,2,2,2,2,
2,2,4),(0.,0.300282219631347,0.600541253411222,0.900368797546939,1.20019367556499,
1.79945360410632,2.39894565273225,3.00286026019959,3.60585654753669,3.75782661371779,
3.90956054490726),.UNSPECIFIED.);
#802=CARTESIAN_POINT('',(8.07537710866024,5.00382699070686,29.6109080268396));
#803=VERTEX_POINT('',#802);
#804=EDGE_CURVE('E444',#803,#776,#801,.T.);
#805=ORIENTED_EDGE('',*,*,#804,.F.);
#806=CARTESIAN_POINT('',(0.,0.,29.6109080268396));
#807=DIRECTION('',(0.,0.,1.));
#808=DIRECTION('',(-1.09310760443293E-09,1.,0.));
#809=AXIS2_PLACEMENT_3D('',#806,#807,#808);
#810=CIRCLE('',#809,9.5);
#811=EDGE_CURVE('E420',#803,#666,#810,.T.);
#812=ORIENTED_EDGE('',*,*,#811,.T.);
#813=EDGE_LOOP('',(#668,#675,#676,#685,#712,#721,#756,#765,#769,#778,#805,#812));
#814=FACE_BOUND('',#813,.T.);
#815=ADVANCED_FACE('F167',(#631,#814),#628,.F.);
#816=CARTESIAN_POINT('',(18.1474454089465,3.75149992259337,13.4105144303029));
#817=CARTESIAN_POINT('',(17.890585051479,3.73467864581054,13.5060281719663));
#818=CARTESIAN_POINT('',(17.6377608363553,3.71812168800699,13.6124268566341));
#819=CARTESIAN_POINT('',(17.1419285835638,3.68565061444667,13.846121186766));
#820=CARTESIAN_POINT('',(16.8989202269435,3.66973647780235,13.9734161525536));
#821=CARTESIAN_POINT('',(16.4245099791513,3.63866828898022,14.2479997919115));
#822=CARTESIAN_POINT('',(16.1931050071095,3.62351403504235,14.395283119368));
#823=CARTESIAN_POINT('',(15.7434802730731,3.5940690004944,14.708832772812));
#824=CARTESIAN_POINT('',(15.5252603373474,3.57977820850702,14.875098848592));
#825=CARTESIAN_POINT('',(15.1034606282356,3.55215537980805,15.2255617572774));
#826=CARTESIAN_POINT('',(14.8998888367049,3.53882386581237,15.4097682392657));
#827=CARTESIAN_POINT('',(14.5090032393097,3.51322554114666,15.7947666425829));
#828=CARTESIAN_POINT('',(14.3216896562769,3.50095874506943,15.9955587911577));
#829=CARTESIAN_POINT('',(13.9647725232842,3.47758494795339,16.4122828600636));
#830=CARTESIAN_POINT('',(13.7951642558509,3.46647763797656,16.628210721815));
#831=CARTESIAN_POINT('',(13.4749045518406,3.44550446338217,17.0737519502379));
#832=CARTESIAN_POINT('',(13.3242529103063,3.43563858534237,17.3033651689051));
#833=CARTESIAN_POINT('',(13.043959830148,3.41728274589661,17.7732237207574));
#834=CARTESIAN_POINT('',(12.9141954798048,3.40878473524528,18.0133954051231));
#835=CARTESIAN_POINT('',(12.6756273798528,3.39316138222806,18.5039680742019));
#836=CARTESIAN_POINT('',(12.5668227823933,3.38603598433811,18.7543686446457));
#837=CARTESIAN_POINT('',(12.3710778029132,3.37321703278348,19.2636307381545));
#838=CARTESIAN_POINT('',(12.2841387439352,3.36752356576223,19.5224927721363));
#839=CARTESIAN_POINT('',(12.1328924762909,3.35761874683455,20.0467739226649));
#840=CARTESIAN_POINT('',(12.06858489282,3.35340737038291,20.3121929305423));
#841=CARTESIAN_POINT('',(11.9641647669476,3.34656910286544,20.8426066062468));
#842=CARTESIAN_POINT('',(11.9236219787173,3.34391403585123,21.1075162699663));
#843=CARTESIAN_POINT('',(11.8652424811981,3.34009087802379,21.6398358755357));
#844=CARTESIAN_POINT('',(11.8474054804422,3.33892276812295,21.9072457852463));
#845=CARTESIAN_POINT('',(11.8345982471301,3.33808404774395,22.4425774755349));
#846=CARTESIAN_POINT('',(11.8396248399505,3.33841322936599,22.7104991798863));
#847=CARTESIAN_POINT('',(11.8724923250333,3.34056565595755,23.2449323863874));
#848=CARTESIAN_POINT('',(11.9003330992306,3.34238889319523,23.5114438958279));
#849=CARTESIAN_POINT('',(11.9780680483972,3.34747960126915,24.0376567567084));
#850=CARTESIAN_POINT('',(12.0276696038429,3.35072790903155,24.2974015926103));
#851=CARTESIAN_POINT('',(12.1484267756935,3.35863605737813,24.8118052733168));
#852=CARTESIAN_POINT('',(12.2195821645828,3.36329588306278,25.0664641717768));
#853=CARTESIAN_POINT('',(12.3828443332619,3.37398759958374,25.5689078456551));
#854=CARTESIAN_POINT('',(12.4749485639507,3.38001932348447,25.8166934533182));
#855=CARTESIAN_POINT('',(12.6794078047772,3.3934089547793,26.3038316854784));
#856=CARTESIAN_POINT('',(12.7917703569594,3.40076735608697,26.5431811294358));
#857=CARTESIAN_POINT('',(13.0369078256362,3.41682092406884,27.0137884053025));
#858=CARTESIAN_POINT('',(13.169851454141,3.4255271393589,27.2449579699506));
#859=CARTESIAN_POINT('',(13.4544154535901,3.44416267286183,27.6954567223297));
#860=CARTESIAN_POINT('',(13.606036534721,3.45409203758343,27.9147854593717));
#861=CARTESIAN_POINT('',(13.9268367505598,3.47510060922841,28.3401572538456));
#862=CARTESIAN_POINT('',(14.0960166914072,3.48617986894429,28.5461997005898));
#863=CARTESIAN_POINT('',(14.4507138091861,3.50940828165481,28.9436423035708));
#864=CARTESIAN_POINT('',(14.6362312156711,3.52155744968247,29.135042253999));
#865=CARTESIAN_POINT('',(15.026026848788,3.54708439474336,29.5054914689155));
#866=CARTESIAN_POINT('',(15.2305978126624,3.56048134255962,29.6842314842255));
#867=CARTESIAN_POINT('',(15.6538967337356,3.58820235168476,30.0239900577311));
#868=CARTESIAN_POINT('',(15.8726245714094,3.60252640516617,30.1850087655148));
#869=CARTESIAN_POINT('',(16.3227525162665,3.63200439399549,30.4882695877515));
#870=CARTESIAN_POINT('',(16.5541555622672,3.64715852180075,30.6305073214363));
#871=CARTESIAN_POINT('',(17.0278914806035,3.67818255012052,30.8951425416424));
#872=CARTESIAN_POINT('',(17.270220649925,3.69405220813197,31.0175466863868));
#873=CARTESIAN_POINT('',(17.7669669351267,3.72658313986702,31.2429802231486));
#874=CARTESIAN_POINT('',(18.0214889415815,3.7432512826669,31.3457775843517));
#875=CARTESIAN_POINT('',(18.5382654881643,3.77709395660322,31.5295393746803));
#876=CARTESIAN_POINT('',(18.8005200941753,3.79426849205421,31.6105036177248));
#877=CARTESIAN_POINT('',(19.3309113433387,3.82900276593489,31.7500060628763));
#878=CARTESIAN_POINT('',(19.5990481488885,3.84656251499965,31.808543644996));
#879=CARTESIAN_POINT('',(20.1392890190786,3.88194182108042,31.9027453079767));
#880=CARTESIAN_POINT('',(20.4113930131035,3.89976137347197,31.9384097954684));
#881=CARTESIAN_POINT('',(20.9576381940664,3.93553388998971,31.9865808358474));
#882=CARTESIAN_POINT('',(21.2317794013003,3.95348685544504,31.9990871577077));
#883=CARTESIAN_POINT('',(21.7801364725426,3.98939767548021,32.0008164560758));
#884=CARTESIAN_POINT('',(22.0543523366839,4.00735553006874,31.9900393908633));
#885=CARTESIAN_POINT('',(22.6008596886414,4.04314521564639,31.9452447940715));
#886=CARTESIAN_POINT('',(22.8731513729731,4.06097705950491,31.9112296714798));
#887=CARTESIAN_POINT('',(23.4138724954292,4.09638781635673,31.8201695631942));
#888=CARTESIAN_POINT('',(23.6823019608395,4.11396673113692,31.7631247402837));
#889=CARTESIAN_POINT('',(24.2118784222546,4.14864764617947,31.6267614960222));
#890=CARTESIAN_POINT('',(24.473057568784,4.1657517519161,31.5475684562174));
#891=CARTESIAN_POINT('',(24.9877954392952,4.19946091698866,31.3673123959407));
#892=CARTESIAN_POINT('',(25.2413540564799,4.21606596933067,31.2662490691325));
#893=CARTESIAN_POINT('',(25.7391278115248,4.24866418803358,31.0428965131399));
#894=CARTESIAN_POINT('',(25.9833385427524,4.26465706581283,30.9205974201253));
#895=CARTESIAN_POINT('',(26.4605066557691,4.29590586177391,30.6556646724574));
#896=CARTESIAN_POINT('',(26.6934645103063,4.31116181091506,30.5130318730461));
#897=CARTESIAN_POINT('',(27.1452633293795,4.34074922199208,30.209224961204));
#898=CARTESIAN_POINT('',(27.3641711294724,4.35508506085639,30.0481506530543));
#899=CARTESIAN_POINT('',(27.7875858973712,4.382813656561,29.7080080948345));
#900=CARTESIAN_POINT('',(27.9920934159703,4.39620644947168,29.5289405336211));
#901=CARTESIAN_POINT('',(28.3848624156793,4.42192811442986,29.1544313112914));
#902=CARTESIAN_POINT('',(28.5731528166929,4.43425888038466,28.9590200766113));
#903=CARTESIAN_POINT('',(28.9324617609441,4.45778931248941,28.5530043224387));
#904=CARTESIAN_POINT('',(29.10349081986,4.46898966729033,28.3424091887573));
#905=CARTESIAN_POINT('',(29.3193740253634,4.48312743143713,28.0522910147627));
#906=CARTESIAN_POINT('',(29.3724491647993,4.48660321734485,27.9788119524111));
#907=CARTESIAN_POINT('',(29.4764415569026,4.49341347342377,27.8304567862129));
#908=CARTESIAN_POINT('',(29.5273611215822,4.49674809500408,27.7555823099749));
#909=CARTESIAN_POINT('',(29.57721810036,4.50001312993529,27.6799920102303));
#910=B_SPLINE_CURVE_WITH_KNOTS('',3,(#816,#817,#818,#819,#820,#821,#822,#823,#824,#825,#826,
#827,#828,#829,#830,#831,#832,#833,#834,#835,#836,#837,#838,#839,#840,#841,#842,#843,#844,#845,
#846,#847,#848,#849,#850,#851,#852,#853,#854,#855,#856,#857,#858,#859,#860,#861,#862,#863,#864,
#865,#866,#867,#868,#869,#870,#871,#872,#873,#874,#875,#876,#877,#878,#879,#880,#881,#882,#883,
#884,#885,#886,#887,#888,#889,#890,#891,#892,#893,#894,#895,#896,#897,#898,#899,#900,#901,#902,
#903,#904,#905,#906,#907,#908,#909),.UNSPECIFIED.,.F.,.F.,(4,2,2,2,2,2,2,2,2,2,2,2,2,2,2,2,2,2,
2,2,2,2,2,2,2,2,2,2,2,2,2,2,2,2,2,2,2,2,2,2,2,2,2,2,2,2,4),(0.,0.82342903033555,
1.64683128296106,2.47001373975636,3.29318534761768,4.1168021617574,4.9404302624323,
5.76383834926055,6.58723753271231,7.40559872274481,8.22392680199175,9.04230438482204,
9.86066841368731,10.6637182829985,11.4667578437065,12.2696859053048,13.0726098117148,
13.8650526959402,14.6574872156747,15.449825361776,16.2424591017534,17.0419728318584,
17.8415169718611,18.6410978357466,19.4406899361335,20.2556974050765,21.0706979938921,
21.8858883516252,22.7008044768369,23.5248358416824,24.3488742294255,25.1729353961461,
25.9969819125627,26.8210366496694,27.64509286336,28.4690636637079,29.2930286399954,
30.1124203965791,30.9318236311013,31.7516084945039,32.5713588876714,33.3868657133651,
34.2023413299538,35.0163312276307,35.8298222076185,36.1019244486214,36.3737270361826),.UNSPECIFIED.);
#911=CARTESIAN_POINT('',(29.57701810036,4.50000003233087,27.6802952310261));
#912=VERTEX_POINT('',#911);
#913=EDGE_CURVE('E272',#767,#912,#910,.T.);
#914=ORIENTED_EDGE('',*,*,#913,.F.);
#915=ORIENTED_EDGE('',*,*,#768,.F.);
#916=CARTESIAN_POINT('',(29.577218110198,-4.50001306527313,27.6799920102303));
#917=CARTESIAN_POINT('',(29.4283813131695,-4.49026603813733,27.9057071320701));
#918=CARTESIAN_POINT('',(29.2699701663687,-4.47989200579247,28.1250732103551));
#919=CARTESIAN_POINT('',(28.9352574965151,-4.4579723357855,28.5496181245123));
#920=CARTESIAN_POINT('',(28.7589571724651,-4.44642677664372,28.7547979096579));
#921=CARTESIAN_POINT('',(28.3898682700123,-4.42225587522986,29.1493363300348));
#922=CARTESIAN_POINT('',(28.1970944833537,-4.40963150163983,29.3387088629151));
#923=CARTESIAN_POINT('',(27.7963194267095,-4.38338553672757,29.700509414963));
#924=CARTESIAN_POINT('',(27.5883182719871,-4.36976395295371,29.8729375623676));
#925=CARTESIAN_POINT('',(27.1584989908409,-4.3416159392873,30.1997036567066));
#926=CARTESIAN_POINT('',(26.9366758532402,-4.32708918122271,30.3540349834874));
#927=CARTESIAN_POINT('',(26.4808650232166,-4.29723903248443,30.6434656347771));
#928=CARTESIAN_POINT('',(26.2468771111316,-4.28191562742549,30.7785646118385));
#929=CARTESIAN_POINT('',(25.7684462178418,-4.25058413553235,31.0285776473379));
#930=CARTESIAN_POINT('',(25.5240048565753,-4.23457615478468,31.1434948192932));
#931=CARTESIAN_POINT('',(25.0263706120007,-4.20198707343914,31.3523874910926));
#932=CARTESIAN_POINT('',(24.7731777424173,-4.18540597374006,31.446363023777));
#933=CARTESIAN_POINT('',(24.2590478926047,-4.15173662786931,31.612996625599));
#934=CARTESIAN_POINT('',(23.9980896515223,-4.13464698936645,31.6855888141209));
#935=CARTESIAN_POINT('',(23.4709078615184,-4.10012289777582,31.8086173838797));
#936=CARTESIAN_POINT('',(23.2046821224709,-4.08268830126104,31.8590443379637));
#937=CARTESIAN_POINT('',(22.6689091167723,-4.04760158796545,31.9373839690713));
#938=CARTESIAN_POINT('',(22.399361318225,-4.02994943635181,31.9652929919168));
#939=CARTESIAN_POINT('',(21.858996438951,-3.99456201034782,31.9984159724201));
#940=CARTESIAN_POINT('',(21.588179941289,-3.97682677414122,32.003639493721));
#941=CARTESIAN_POINT('',(21.0454404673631,-3.94128384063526,31.9913795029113));
#942=CARTESIAN_POINT('',(20.7735205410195,-3.92347634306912,31.9737602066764));
#943=CARTESIAN_POINT('',(20.232112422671,-3.88802059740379,31.9157373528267));
#944=CARTESIAN_POINT('',(19.9626242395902,-3.87037234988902,31.8753337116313));
#945=CARTESIAN_POINT('',(19.4280257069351,-3.83536255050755,31.7720671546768));
#946=CARTESIAN_POINT('',(19.1629144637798,-3.81800094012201,31.7092088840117));
#947=CARTESIAN_POINT('',(18.6387730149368,-3.78367595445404,31.5614710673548));
#948=CARTESIAN_POINT('',(18.3797450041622,-3.76671272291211,31.4765837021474));
#949=CARTESIAN_POINT('',(17.8682212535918,-3.73321404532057,31.2848646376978));
#950=CARTESIAN_POINT('',(17.6157711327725,-3.7166815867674,31.1779106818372));
#951=CARTESIAN_POINT('',(17.1207308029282,-3.68426237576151,30.9431230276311));
#952=CARTESIAN_POINT('',(16.878140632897,-3.66837562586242,30.8152892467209));
#953=CARTESIAN_POINT('',(16.4045275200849,-3.63735964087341,30.5396362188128));
#954=CARTESIAN_POINT('',(16.1735051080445,-3.62223044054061,30.3918160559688));
#955=CARTESIAN_POINT('',(15.7246795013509,-3.59283774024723,30.0772205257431));
#956=CARTESIAN_POINT('',(15.5068766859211,-3.57857426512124,29.9104446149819));
#957=CARTESIAN_POINT('',(15.0856203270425,-3.55098702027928,29.5587225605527));
#958=CARTESIAN_POINT('',(14.8821981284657,-3.53766530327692,29.3737387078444));
#959=CARTESIAN_POINT('',(14.4917116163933,-3.51209311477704,28.9871837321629));
#960=CARTESIAN_POINT('',(14.3046468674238,-3.49984261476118,28.7856130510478));
#961=CARTESIAN_POINT('',(13.948272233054,-3.47650434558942,28.367276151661));
#962=CARTESIAN_POINT('',(13.7789624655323,-3.46541658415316,28.1505098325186));
#963=CARTESIAN_POINT('',(13.4594078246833,-3.44448958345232,27.7032976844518));
#964=CARTESIAN_POINT('',(13.3091626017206,-3.43465032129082,27.4728521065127));
#965=CARTESIAN_POINT('',(13.0300075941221,-3.416369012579,27.0017206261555));
#966=CARTESIAN_POINT('',(12.9009427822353,-3.40791681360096,26.7611269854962));
#967=CARTESIAN_POINT('',(12.6638563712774,-3.39239049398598,26.2698561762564));
#968=CARTESIAN_POINT('',(12.55582645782,-3.38531582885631,26.0191830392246));
#969=CARTESIAN_POINT('',(12.3616487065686,-3.37259951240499,25.5094385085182));
#970=CARTESIAN_POINT('',(12.2755026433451,-3.36695797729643,25.2503664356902));
#971=CARTESIAN_POINT('',(12.1258566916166,-3.35715796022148,24.7257346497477));
#972=CARTESIAN_POINT('',(12.0623564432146,-3.35299945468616,24.4601750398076));
#973=CARTESIAN_POINT('',(11.9595441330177,-3.34626648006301,23.9295575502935));
#974=CARTESIAN_POINT('',(11.9198013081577,-3.34366380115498,23.6645834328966));
#975=CARTESIAN_POINT('',(11.8630211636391,-3.33994538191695,23.1322038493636));
#976=CARTESIAN_POINT('',(11.8459835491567,-3.33882962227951,22.8647984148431));
#977=CARTESIAN_POINT('',(11.8347668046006,-3.33809505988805,22.3295252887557));
#978=CARTESIAN_POINT('',(11.8405861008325,-3.33847615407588,22.061657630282));
#979=CARTESIAN_POINT('',(11.875027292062,-3.34073163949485,21.5273997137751));
#980=CARTESIAN_POINT('',(11.9036490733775,-3.34260602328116,21.2610094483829));
#981=CARTESIAN_POINT('',(11.9829240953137,-3.34779758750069,20.7350583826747));
#982=CARTESIAN_POINT('',(12.0332886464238,-3.35109586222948,20.475453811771));
#983=CARTESIAN_POINT('',(12.1555550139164,-3.35910284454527,19.9613934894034));
#984=CARTESIAN_POINT('',(12.2274566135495,-3.36381153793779,19.7069376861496));
#985=CARTESIAN_POINT('',(12.3921774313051,-3.37459877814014,19.2049950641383));
#986=CARTESIAN_POINT('',(12.4849912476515,-3.38067697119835,18.9575064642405));
#987=CARTESIAN_POINT('',(12.6908448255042,-3.39415791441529,18.4709993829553));
#988=CARTESIAN_POINT('',(12.8038936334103,-3.40156125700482,18.2319847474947));
#989=CARTESIAN_POINT('',(13.0503991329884,-3.41770441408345,17.7620583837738));
#990=CARTESIAN_POINT('',(13.1840279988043,-3.42645550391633,17.5312373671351));
#991=CARTESIAN_POINT('',(13.4698675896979,-3.44517457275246,17.0815911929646));
#992=CARTESIAN_POINT('',(13.6220707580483,-3.4551420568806,16.8627612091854));
#993=CARTESIAN_POINT('',(13.9440945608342,-3.47623075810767,16.4382825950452));
#994=CARTESIAN_POINT('',(14.1139279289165,-3.48735280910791,16.2326436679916));
#995=CARTESIAN_POINT('',(14.4698944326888,-3.51066435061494,15.8360721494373));
#996=CARTESIAN_POINT('',(14.6560271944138,-3.52285381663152,15.6451392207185));
#997=CARTESIAN_POINT('',(15.0471805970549,-3.54846967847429,15.2755429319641));
#998=CARTESIAN_POINT('',(15.2525053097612,-3.56191598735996,15.0972026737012));
#999=CARTESIAN_POINT('',(15.6772923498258,-3.58973444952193,14.7583242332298));
#1000=CARTESIAN_POINT('',(15.8967545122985,-3.60410659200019,14.5977858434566));
#1001=CARTESIAN_POINT('',(16.347893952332,-3.63365082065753,14.2958496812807));
#1002=CARTESIAN_POINT('',(16.5795509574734,-3.648821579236,14.1544214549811));
#1003=CARTESIAN_POINT('',(17.053703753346,-3.67987290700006,13.8914238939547));
#1004=CARTESIAN_POINT('',(17.2961933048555,-3.69575306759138,13.7698433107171));
#1005=CARTESIAN_POINT('',(17.6425873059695,-3.71843772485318,13.6138611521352));
#1006=CARTESIAN_POINT('',(17.7426773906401,-3.72499242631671,13.5707938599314));
#1007=CARTESIAN_POINT('',(17.9441132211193,-3.73818406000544,13.4880908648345));
#1008=CARTESIAN_POINT('',(18.0454572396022,-3.74482087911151,13.4484509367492));
#1009=CARTESIAN_POINT('',(18.1474454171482,-3.75149988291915,13.4105144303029));
#1010=B_SPLINE_CURVE_WITH_KNOTS('',3,(#916,#917,#918,#919,#920,#921,#922,#923,#924,#925,#926,
#927,#928,#929,#930,#931,#932,#933,#934,#935,#936,#937,#938,#939,#940,#941,#942,#943,#944,#945,
#946,#947,#948,#949,#950,#951,#952,#953,#954,#955,#956,#957,#958,#959,#960,#961,#962,#963,#964,
#965,#966,#967,#968,#969,#970,#971,#972,#973,#974,#975,#976,#977,#978,#979,#980,#981,#982,#983,
#984,#985,#986,#987,#988,#989,#990,#991,#992,#993,#994,#995,#996,#997,#998,#999,#1000,#1001,
#1002,#1003,#1004,#1005,#1006,#1007,#1008,#1009),.UNSPECIFIED.,.F.,.F.,(4,2,2,2,2,2,2,2,2,2,2,2,
2,2,2,2,2,2,2,2,2,2,2,2,2,2,2,2,2,2,2,2,2,2,2,2,2,2,2,2,2,2,2,2,2,2,4),(0.,0.811383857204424,
1.62271336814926,2.43332187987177,3.2439242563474,4.05482224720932,4.86573488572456,
5.6765223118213,6.48730846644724,7.3005670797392,8.11417124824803,8.92790742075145,
9.74130050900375,10.5595508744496,11.3778042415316,12.1958884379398,13.0142634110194,
13.8373004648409,14.6603407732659,15.4834188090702,16.3065204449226,17.1313641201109,
17.9561858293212,18.7810130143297,19.6058250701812,20.4243011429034,21.242453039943,
22.060671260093,22.8788764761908,23.6817568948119,24.4846268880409,25.2874416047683,
26.0902523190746,26.8827166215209,27.6751729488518,28.4674248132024,29.2600317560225,
30.0596712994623,30.8589865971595,31.6588832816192,32.4587616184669,33.2746912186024,
34.0906113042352,34.905215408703,35.7193562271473,36.0467859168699,36.3738060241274),.UNSPECIFIED.);
#1011=CARTESIAN_POINT('',(29.577018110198,-4.49999996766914,27.6802952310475));
#1012=VERTEX_POINT('',#1011);
#1013=EDGE_CURVE('E241',#1012,#763,#1010,.T.);
#1014=ORIENTED_EDGE('',*,*,#1013,.F.);
#1015=CARTESIAN_POINT('',(31.3695646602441,-2.86363632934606,22.4));
#1016=CARTESIAN_POINT('',(31.3693228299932,-2.86628555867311,22.4059654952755));
#1017=CARTESIAN_POINT('',(31.3690751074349,-2.86893434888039,22.4119311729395));
#1018=CARTESIAN_POINT('',(31.3455550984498,-3.11453940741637,22.9652019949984));
#1019=CARTESIAN_POINT('',(31.2727100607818,-3.35362318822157,23.5139845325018));
#1020=CARTESIAN_POINT('',(31.0906514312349,-3.68216337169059,24.3317563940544));
#1021=CARTESIAN_POINT('',(31.0177760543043,-3.78670942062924,24.6035877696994));
#1022=CARTESIAN_POINT('',(30.8477677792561,-3.98135438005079,25.1449637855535));
#1023=CARTESIAN_POINT('',(30.7506472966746,-4.07146064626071,25.4145095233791));
#1024=CARTESIAN_POINT('',(30.57193326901,-4.202528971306,25.8529322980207));
#1025=CARTESIAN_POINT('',(30.4974342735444,-4.24947679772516,26.0229493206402));
#1026=CARTESIAN_POINT('',(30.338874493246,-4.3332827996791,26.3608778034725));
#1027=CARTESIAN_POINT('',(30.2548212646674,-4.37014887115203,26.5287908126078));
#1028=CARTESIAN_POINT('',(30.0769796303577,-4.43174326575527,26.8627513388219));
#1029=CARTESIAN_POINT('',(29.9831491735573,-4.45641629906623,27.0287870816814));
#1030=CARTESIAN_POINT('',(29.8357178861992,-4.48201224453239,27.2752518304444));
#1031=CARTESIAN_POINT('',(29.7853951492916,-4.48864303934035,27.3570723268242));
#1032=CARTESIAN_POINT('',(29.6826484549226,-4.49763621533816,27.5196657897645));
#1033=CARTESIAN_POINT('',(29.6302236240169,-4.49999680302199,27.6004383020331));
#1034=CARTESIAN_POINT('',(29.5768181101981,-4.49999995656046,27.6805954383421));
#1035=B_SPLINE_CURVE_WITH_KNOTS('',3,(#1015,#1016,#1017,#1018,#1019,#1020,#1021,#1022,#1023,
#1024,#1025,#1026,#1027,#1028,#1029,#1030,#1031,#1032,#1033,#1034),.UNSPECIFIED.,.F.,.F.,(4,2,2,
2,2,2,2,2,2,4),(0.,0.0195959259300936,1.81731826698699,2.7171233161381,3.6164685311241,
4.19044381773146,4.76396827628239,5.34007007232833,5.62881792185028,5.91768701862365),.UNSPECIFIED.);
#1036=CARTESIAN_POINT('',(31.3695646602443,-2.86363632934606,22.4));
#1037=VERTEX_POINT('',#1036);
#1038=EDGE_CURVE('E318',#1037,#1012,#1035,.T.);
#1039=ORIENTED_EDGE('',*,*,#1038,.F.);
#1040=CARTESIAN_POINT('',(29.576818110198,-4.49999995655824,17.119404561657));
#1041=CARTESIAN_POINT('',(29.6191393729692,-4.50000099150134,17.1829266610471));
#1042=CARTESIAN_POINT('',(29.6608485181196,-4.4985171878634,17.2468391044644));
#1043=CARTESIAN_POINT('',(29.7429683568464,-4.49280696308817,17.3753522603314));
#1044=CARTESIAN_POINT('',(29.7833793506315,-4.48858118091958,17.4399528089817));
#1045=CARTESIAN_POINT('',(29.9024609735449,-4.47214702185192,17.6344933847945));
#1046=CARTESIAN_POINT('',(29.9791105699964,-4.4561804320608,17.765367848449));
#1047=CARTESIAN_POINT('',(30.1263186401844,-4.4158292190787,18.0284830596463));
#1048=CARTESIAN_POINT('',(30.1969002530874,-4.39147852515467,18.1607162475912));
#1049=CARTESIAN_POINT('',(30.3321494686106,-4.33558285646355,18.4267422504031));
#1050=CARTESIAN_POINT('',(30.3968138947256,-4.30403404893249,18.5605358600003));
#1051=CARTESIAN_POINT('',(30.5626786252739,-4.21088532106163,18.9222641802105));
#1052=CARTESIAN_POINT('',(30.658240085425,-4.14358637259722,19.1513508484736));
#1053=CARTESIAN_POINT('',(30.8316829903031,-3.9956894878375,19.6118454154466));
#1054=CARTESIAN_POINT('',(30.9095558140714,-3.91508509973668,19.8432543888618));
#1055=CARTESIAN_POINT('',(31.1166837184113,-3.65806715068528,20.5407057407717));
#1056=CARTESIAN_POINT('',(31.2192514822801,-3.46657221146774,21.0095421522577));
#1057=CARTESIAN_POINT('',(31.3069727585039,-3.20184753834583,21.6292554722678));
#1058=CARTESIAN_POINT('',(31.3245600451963,-3.13661932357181,21.7798368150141));
#1059=CARTESIAN_POINT('',(31.3522803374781,-3.0048998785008,22.0809896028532));
#1060=CARTESIAN_POINT('',(31.362422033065,-2.93841021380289,22.2315608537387));
#1061=CARTESIAN_POINT('',(31.3690750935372,-2.8689344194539,22.3880686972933));
#1062=CARTESIAN_POINT('',(31.3693228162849,-2.86628562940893,22.3940343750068));
#1063=CARTESIAN_POINT('',(31.3695646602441,-2.86363632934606,22.4));
#1064=B_SPLINE_CURVE_WITH_KNOTS('',3,(#1040,#1041,#1042,#1043,#1044,#1045,#1046,#1047,#1048,
#1049,#1050,#1051,#1052,#1053,#1054,#1055,#1056,#1057,#1058,#1059,#1060,#1061,#1062,#1063),
.UNSPECIFIED.,.F.,.F.,(4,2,2,2,2,2,2,2,2,2,2,4),(0.,0.228945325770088,0.457837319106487,
0.914918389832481,1.37017104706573,1.8256666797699,2.59598824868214,3.36668444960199,
4.90952775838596,5.40460012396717,5.8990937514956,5.91868967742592),.UNSPECIFIED.);
#1065=CARTESIAN_POINT('',(29.577018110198,-4.49999996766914,17.1197047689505));
#1066=VERTEX_POINT('',#1065);
#1067=EDGE_CURVE('E310',#1066,#1037,#1064,.T.);
#1068=ORIENTED_EDGE('',*,*,#1067,.F.);
#1069=CARTESIAN_POINT('',(24.9182172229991,-4.19490432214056,13.4105144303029));
#1070=CARTESIAN_POINT('',(25.1747287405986,-4.21170275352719,13.5063205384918));
#1071=CARTESIAN_POINT('',(25.4271515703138,-4.22823342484,13.6131252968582));
#1072=CARTESIAN_POINT('',(25.9220334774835,-4.26064226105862,13.847863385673));
#1073=CARTESIAN_POINT('',(26.1644920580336,-4.27652039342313,13.9757977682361));
#1074=CARTESIAN_POINT('',(26.6315223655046,-4.30710528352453,14.2483504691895));
#1075=CARTESIAN_POINT('',(26.8563943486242,-4.32183170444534,14.3924524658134));
#1076=CARTESIAN_POINT('',(27.2933789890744,-4.35044896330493,14.6988790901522));
#1077=CARTESIAN_POINT('',(27.5054935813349,-4.36433992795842,14.8612009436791));
#1078=CARTESIAN_POINT('',(27.8883161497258,-4.38941021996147,15.1803070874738));
#1079=CARTESIAN_POINT('',(28.0607864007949,-4.40070495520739,15.3349749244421));
#1080=CARTESIAN_POINT('',(28.3941147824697,-4.42253397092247,15.6563910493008));
#1081=CARTESIAN_POINT('',(28.5549737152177,-4.43306830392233,15.8231385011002));
#1082=CARTESIAN_POINT('',(28.8677866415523,-4.45355380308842,16.171824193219));
#1083=CARTESIAN_POINT('',(29.0194509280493,-4.463485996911,16.3540235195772));
#1084=CARTESIAN_POINT('',(29.3089338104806,-4.4824436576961,16.7291933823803));
#1085=CARTESIAN_POINT('',(29.4467504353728,-4.49146899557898,16.9221654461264));
#1086=CARTESIAN_POINT('',(29.577218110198,-4.50001306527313,17.1200079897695));
#1087=B_SPLINE_CURVE_WITH_KNOTS('',3,(#1069,#1070,#1071,#1072,#1073,#1074,#1075,#1076,#1077,
#1078,#1079,#1080,#1081,#1082,#1083,#1084,#1085,#1086),.UNSPECIFIED.,.F.,.F.,(4,2,2,2,2,2,2,2,
4),(0.,0.82275942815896,1.64555983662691,2.44710662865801,3.24853154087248,3.9437587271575,
4.63893783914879,5.35009750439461,6.06135825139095),.UNSPECIFIED.);
#1088=EDGE_CURVE('E235',#458,#1066,#1087,.T.);
#1089=ORIENTED_EDGE('',*,*,#1088,.F.);
#1090=ORIENTED_EDGE('',*,*,#459,.T.);
#1091=CARTESIAN_POINT('',(29.57721810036,4.50001312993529,17.1200079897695));
#1092=CARTESIAN_POINT('',(29.4265102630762,4.49014357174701,16.8914517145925));
#1093=CARTESIAN_POINT('',(29.265980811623,4.47963081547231,16.6694035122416));
#1094=CARTESIAN_POINT('',(28.9265816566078,4.45740423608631,16.2398574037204));
#1095=CARTESIAN_POINT('',(28.7477118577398,4.44569040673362,16.0323595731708));
#1096=CARTESIAN_POINT('',(28.3777669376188,4.42146344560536,15.6385921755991));
#1097=CARTESIAN_POINT('',(28.1871252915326,4.40897870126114,15.451913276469));
#1098=CARTESIAN_POINT('',(27.7910307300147,4.38303925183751,15.0951091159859));
#1099=CARTESIAN_POINT('',(27.5855798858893,4.36958468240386,14.9249815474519));
#1100=CARTESIAN_POINT('',(27.1888740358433,4.34360520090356,14.623387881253));
#1101=CARTESIAN_POINT('',(26.9992422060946,4.33118658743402,14.4897704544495));
#1102=CARTESIAN_POINT('',(26.6108442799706,4.30575117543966,14.2366062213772));
#1103=CARTESIAN_POINT('',(26.4120783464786,4.29273438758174,14.1170591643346));
#1104=CARTESIAN_POINT('',(26.0017910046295,4.26586548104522,13.8900697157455));
#1105=CARTESIAN_POINT('',(25.7900813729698,4.25200103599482,13.7829689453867));
#1106=CARTESIAN_POINT('',(25.3593415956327,4.22379273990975,13.5846713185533));
#1107=CARTESIAN_POINT('',(25.1403106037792,4.2094488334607,13.4934763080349));
#1108=CARTESIAN_POINT('',(24.9182172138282,4.19490437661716,13.4105144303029));
#1109=B_SPLINE_CURVE_WITH_KNOTS('',3,(#1091,#1092,#1093,#1094,#1095,#1096,#1097,#1098,#1099,
#1100,#1101,#1102,#1103,#1104,#1105,#1106,#1107,#1108),.UNSPECIFIED.,.F.,.F.,(4,2,2,2,2,2,2,2,
4),(0.,0.821594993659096,1.64319425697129,2.44361485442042,3.2439237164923,3.94026355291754,
4.63659097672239,5.34893288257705,6.0613574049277),.UNSPECIFIED.);
#1110=CARTESIAN_POINT('',(29.57701810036,4.50000003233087,17.1197047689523));
#1111=VERTEX_POINT('',#1110);
#1112=EDGE_CURVE('E35',#1111,#454,#1109,.T.);
#1113=ORIENTED_EDGE('',*,*,#1112,.F.);
#1114=CARTESIAN_POINT('',(31.3695646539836,2.86363639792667,22.4));
#1115=CARTESIAN_POINT('',(31.3693228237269,2.86628562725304,22.3940345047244));
#1116=CARTESIAN_POINT('',(31.3690751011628,2.86893441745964,22.3880688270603));
#1117=CARTESIAN_POINT('',(31.3455550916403,3.11453947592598,21.8347980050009));
#1118=CARTESIAN_POINT('',(31.2727100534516,3.35362325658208,21.2860154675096));
#1119=CARTESIAN_POINT('',(31.0906514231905,3.68216343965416,20.4682436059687));
#1120=CARTESIAN_POINT('',(31.017776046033,3.78670948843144,20.1964122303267));
#1121=CARTESIAN_POINT('',(30.8477677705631,3.98135444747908,19.6550362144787));
#1122=CARTESIAN_POINT('',(30.7506472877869,4.07146071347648,19.3854904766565));
#1123=CARTESIAN_POINT('',(30.5719332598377,4.20252903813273,18.947067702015));
#1124=CARTESIAN_POINT('',(30.4974342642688,4.24947686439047,18.7770506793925));
#1125=CARTESIAN_POINT('',(30.3388744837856,4.33328286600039,18.4391221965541));
#1126=CARTESIAN_POINT('',(30.2548212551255,4.37014893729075,18.2712091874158));
#1127=CARTESIAN_POINT('',(30.0769796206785,4.43174333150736,17.9372486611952));
#1128=CARTESIAN_POINT('',(29.9831491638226,4.45641636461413,17.7712129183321));
#1129=CARTESIAN_POINT('',(29.8357178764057,4.48201230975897,17.524748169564));
#1130=CARTESIAN_POINT('',(29.7853951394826,4.48864310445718,17.4429276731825));
#1131=CARTESIAN_POINT('',(29.6826484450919,4.49763628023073,17.2803342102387));
#1132=CARTESIAN_POINT('',(29.63022361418,4.49999686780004,17.1995616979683));
#1133=CARTESIAN_POINT('',(29.5768181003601,4.50000002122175,17.1194045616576));
#1134=B_SPLINE_CURVE_WITH_KNOTS('',3,(#1114,#1115,#1116,#1117,#1118,#1119,#1120,#1121,#1122,
#1123,#1124,#1125,#1126,#1127,#1128,#1129,#1130,#1131,#1132,#1133),.UNSPECIFIED.,.F.,.F.,(4,2,2,
2,2,2,2,2,2,4),(0.,0.0195959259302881,1.81731826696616,2.7171233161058,3.61646853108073,
4.19044381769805,4.76396827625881,5.34007007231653,5.62881792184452,5.91768701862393),.UNSPECIFIED.);
#1135=CARTESIAN_POINT('',(31.3695646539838,2.86363639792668,22.4));
#1136=VERTEX_POINT('',#1135);
#1137=EDGE_CURVE('E332',#1136,#1111,#1134,.T.);
#1138=ORIENTED_EDGE('',*,*,#1137,.F.);
#1139=CARTESIAN_POINT('',(29.57681810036,4.50000002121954,27.6805954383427));
#1140=CARTESIAN_POINT('',(29.6191393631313,4.50000105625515,27.6170733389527));
#1141=CARTESIAN_POINT('',(29.660848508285,4.4985172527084,27.5531608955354));
#1142=CARTESIAN_POINT('',(29.7429683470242,4.49280702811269,27.4246477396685));
#1143=CARTESIAN_POINT('',(29.7833793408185,4.48858124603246,27.3600471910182));
#1144=CARTESIAN_POINT('',(29.9024609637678,4.47214708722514,27.1655066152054));
#1145=CARTESIAN_POINT('',(29.9791105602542,4.4561804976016,27.0346321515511));
#1146=CARTESIAN_POINT('',(30.1263186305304,4.41582928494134,26.7715169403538));
#1147=CARTESIAN_POINT('',(30.1969002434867,4.3914785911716,26.6392837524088));
#1148=CARTESIAN_POINT('',(30.3321494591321,4.33558292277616,26.3732577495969));
#1149=CARTESIAN_POINT('',(30.396813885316,4.30403411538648,26.2394641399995));
#1150=CARTESIAN_POINT('',(30.562678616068,4.21088538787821,25.8777358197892));
#1151=CARTESIAN_POINT('',(30.6582400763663,4.14358643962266,25.6486491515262));
#1152=CARTESIAN_POINT('',(30.8316829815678,3.99568955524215,25.1881545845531));
#1153=CARTESIAN_POINT('',(30.9095558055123,3.91508516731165,24.9567456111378));
#1154=CARTESIAN_POINT('',(31.116683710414,3.65806721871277,24.2592942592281));
#1155=CARTESIAN_POINT('',(31.2192514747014,3.46657227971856,23.7904578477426));
#1156=CARTESIAN_POINT('',(31.306972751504,3.20184760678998,23.1707445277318));
#1157=CARTESIAN_POINT('',(31.3245600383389,3.13661939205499,23.0201631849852));
#1158=CARTESIAN_POINT('',(31.3522803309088,3.00489994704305,22.7190103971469));
#1159=CARTESIAN_POINT('',(31.3624220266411,2.93841028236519,22.5684391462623));
#1160=CARTESIAN_POINT('',(31.3690750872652,2.86893448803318,22.4119313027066));
#1161=CARTESIAN_POINT('',(31.3693228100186,2.86628569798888,22.4059656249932));
#1162=CARTESIAN_POINT('',(31.3695646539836,2.86363639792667,22.4));
#1163=B_SPLINE_CURVE_WITH_KNOTS('',3,(#1139,#1140,#1141,#1142,#1143,#1144,#1145,#1146,#1147,
#1148,#1149,#1150,#1151,#1152,#1153,#1154,#1155,#1156,#1157,#1158,#1159,#1160,#1161,#1162),
.UNSPECIFIED.,.F.,.F.,(4,2,2,2,2,2,2,2,2,2,2,4),(0.,0.228945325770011,0.45783731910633,
0.91491838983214,1.37017104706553,1.82566667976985,2.59598824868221,3.36668444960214,
4.90952775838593,5.40460012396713,5.89909375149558,5.9186896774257),.UNSPECIFIED.);
#1164=EDGE_CURVE('E325',#912,#1136,#1163,.T.);
#1165=ORIENTED_EDGE('',*,*,#1164,.F.);
#1166=EDGE_LOOP('',(#914,#915,#1014,#1039,#1068,#1089,#1090,#1113,#1138,#1165));
#1167=FACE_BOUND('',#1166,.T.);
#1168=ADVANCED_FACE('F254',(#1167),#23,.T.);
#1169=CARTESIAN_POINT('',(-11.3705729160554,3.3076959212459,8.11550848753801));
#1170=CARTESIAN_POINT('',(-13.3194357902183,3.43532309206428,8.65165350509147));
#1171=CARTESIAN_POINT('',(-15.2454387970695,3.56145321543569,9.27335320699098));
#1172=CARTESIAN_POINT('',(-19.0285581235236,3.80920220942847,10.6774595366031));
#1173=CARTESIAN_POINT('',(-20.8859409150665,3.93083853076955,11.4591449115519));
#1174=CARTESIAN_POINT('',(-23.0778618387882,4.07438309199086,12.4939591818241));
#1175=CARTESIAN_POINT('',(-23.4481408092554,4.09863192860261,12.6727423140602));
#1176=CARTESIAN_POINT('',(-24.1858660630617,4.14694409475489,13.0369148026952));
#1177=CARTESIAN_POINT('',(-24.5533094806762,4.17100723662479,13.2223099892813));
#1178=CARTESIAN_POINT('',(-24.9191403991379,4.19496477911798,13.4109144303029));
#1179=B_SPLINE_CURVE_WITH_KNOTS('',3,(#1169,#1170,#1171,#1172,#1173,#1174,#1175,#1176,#1177,
#1178),.UNSPECIFIED.,.F.,.F.,(4,2,2,2,4),(0.,6.07517314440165,12.1235385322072,13.3591937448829,
14.5959668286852),.UNSPECIFIED.);
#1180=CARTESIAN_POINT('',(-11.3707729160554,3.3077090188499,8.11556349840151));
#1181=VERTEX_POINT('',#1180);
#1182=EDGE_CURVE('E379',#1181,#307,#1179,.T.);
#1183=ORIENTED_EDGE('',*,*,#1182,.F.);
#1184=CARTESIAN_POINT('',(-11.3709729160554,3.30772212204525,8.11561851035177));
#1185=CARTESIAN_POINT('',(-11.2701325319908,3.30110508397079,8.08788118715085));
#1186=CARTESIAN_POINT('',(-11.1688817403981,3.29874080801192,8.06061250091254));
#1187=CARTESIAN_POINT('',(-10.9662236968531,3.30257078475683,8.00721735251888));
#1188=CARTESIAN_POINT('',(-10.8648164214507,3.30876647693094,7.98109108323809));
#1189=CARTESIAN_POINT('',(-10.6624409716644,3.32978236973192,7.93016922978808));
#1190=CARTESIAN_POINT('',(-10.5614733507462,3.34461136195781,7.9053750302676));
#1191=CARTESIAN_POINT('',(-10.3608328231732,3.38287017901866,7.85737208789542));
#1192=CARTESIAN_POINT('',(-10.2611598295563,3.40629942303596,7.83416323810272));
#1193=CARTESIAN_POINT('',(-9.96486870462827,3.48949810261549,7.76717843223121));
#1194=CARTESIAN_POINT('',(-9.77109378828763,3.56216661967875,7.72607333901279));
#1195=CARTESIAN_POINT('',(-9.39755023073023,3.74054377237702,7.65286990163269));
#1196=CARTESIAN_POINT('',(-9.2177767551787,3.84624094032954,7.62076843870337));
#1197=CARTESIAN_POINT('',(-8.96611053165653,4.02532516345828,7.58103605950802));
#1198=CARTESIAN_POINT('',(-8.88646307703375,4.08719629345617,7.56933067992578));
#1199=CARTESIAN_POINT('',(-8.7324559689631,4.21758209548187,7.54853793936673));
#1200=CARTESIAN_POINT('',(-8.65809406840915,4.28609391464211,7.53944946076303));
#1201=CARTESIAN_POINT('',(-8.51538278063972,4.4291678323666,7.52402786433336));
#1202=CARTESIAN_POINT('',(-8.44702397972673,4.50372009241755,7.51769036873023));
#1203=CARTESIAN_POINT('',(-8.3167724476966,4.65839173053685,7.50784180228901));
#1204=CARTESIAN_POINT('',(-8.25487550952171,4.7385074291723,7.50432888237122));
#1205=CARTESIAN_POINT('',(-8.17532776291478,4.85096453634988,7.5015002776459));
#1206=CARTESIAN_POINT('',(-8.15464680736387,4.88116889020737,7.50093670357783));
#1207=CARTESIAN_POINT('',(-8.11423875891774,4.94215937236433,7.50018643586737));
#1208=CARTESIAN_POINT('',(-8.09451050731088,4.97294472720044,7.49999927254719));
#1209=CARTESIAN_POINT('',(-8.07525306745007,5.00402718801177,7.50000000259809));
#1210=B_SPLINE_CURVE_WITH_KNOTS('',3,(#1184,#1185,#1186,#1187,#1188,#1189,#1190,#1191,#1192,
#1193,#1194,#1195,#1196,#1197,#1198,#1199,#1200,#1201,#1202,#1203,#1204,#1205,#1206,#1207,#1208,
#1209),.UNSPECIFIED.,.F.,.F.,(4,2,2,2,2,2,2,2,2,2,2,2,4),(0.,0.314298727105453,
0.628650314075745,0.943322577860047,1.25797359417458,1.88762970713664,2.51706744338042,
2.8213430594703,3.12548853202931,3.42914821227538,3.73260894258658,3.84242585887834,
3.95210566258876),.UNSPECIFIED.);
#1211=CARTESIAN_POINT('',(-8.07537698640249,5.00382718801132,7.5));
#1212=VERTEX_POINT('',#1211);
#1213=EDGE_CURVE('E513',#1181,#1212,#1210,.T.);
#1214=ORIENTED_EDGE('',*,*,#1213,.T.);
#1215=CARTESIAN_POINT('',(-8.07537699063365,-5.00382718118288,7.5));
#1216=VERTEX_POINT('',#1215);
#1217=EDGE_CURVE('E179',#1212,#1216,#406,.T.);
#1218=ORIENTED_EDGE('',*,*,#1217,.T.);
#1219=CARTESIAN_POINT('',(-8.07525307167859,-5.00402718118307,7.50000000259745));
#1220=CARTESIAN_POINT('',(-8.12665441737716,-4.92103792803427,7.49999174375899));
#1221=CARTESIAN_POINT('',(-8.18144847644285,-4.84015839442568,7.50133541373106));
#1222=CARTESIAN_POINT('',(-8.29736168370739,-4.6831802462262,7.50668033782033));
#1223=CARTESIAN_POINT('',(-8.35847975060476,-4.60708081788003,7.51068113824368));
#1224=CARTESIAN_POINT('',(-8.48644165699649,-4.46037546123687,7.52128108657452));
#1225=CARTESIAN_POINT('',(-8.55327111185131,-4.38975653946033,7.52787384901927));
#1226=CARTESIAN_POINT('',(-8.69224285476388,-4.25429572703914,7.5435639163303));
#1227=CARTESIAN_POINT('',(-8.7643851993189,-4.18945389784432,7.55266124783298));
#1228=CARTESIAN_POINT('',(-8.98795737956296,-4.00427143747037,7.58354717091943));
#1229=CARTESIAN_POINT('',(-9.1466738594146,-3.89311225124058,7.60894165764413));
#1230=CARTESIAN_POINT('',(-9.47864023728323,-3.69815746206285,7.66816072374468));
#1231=CARTESIAN_POINT('',(-9.65189867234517,-3.61437807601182,7.70199027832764));
#1232=CARTESIAN_POINT('',(-10.0125622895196,-3.47403579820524,7.77763324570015));
#1233=CARTESIAN_POINT('',(-10.2002111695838,-3.41819613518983,7.81962319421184));
#1234=CARTESIAN_POINT('',(-10.5805890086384,-3.33774348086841,7.90948191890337));
#1235=CARTESIAN_POINT('',(-10.7733128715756,-3.31310029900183,7.95734496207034));
#1236=CARTESIAN_POINT('',(-11.0336533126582,-3.30081514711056,8.02491668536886));
#1237=CARTESIAN_POINT('',(-11.1013246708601,-3.29954055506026,8.04274726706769));
#1238=CARTESIAN_POINT('',(-11.2363731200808,-3.30079632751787,8.07885367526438));
#1239=CARTESIAN_POINT('',(-11.3037505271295,-3.30331933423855,8.09712857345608));
#1240=CARTESIAN_POINT('',(-11.370972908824,-3.30772214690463,8.11561851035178));
#1241=B_SPLINE_CURVE_WITH_KNOTS('',3,(#1219,#1220,#1221,#1222,#1223,#1224,#1225,#1226,#1227,
#1228,#1229,#1230,#1231,#1232,#1233,#1234,#1235,#1236,#1237,#1238,#1239,#1240),.UNSPECIFIED.,
.F.,.F.,(4,2,2,2,2,2,2,2,2,2,4),(0.,0.292752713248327,0.585455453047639,0.877441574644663,
1.16943080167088,1.75277205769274,2.33645819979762,2.93455893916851,3.53208041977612,
3.74198081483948,3.95147505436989),.UNSPECIFIED.);
#1242=CARTESIAN_POINT('',(-11.370772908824,-3.30770904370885,8.11556349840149));
#1243=VERTEX_POINT('',#1242);
#1244=EDGE_CURVE('E529',#1216,#1243,#1241,.T.);
#1245=ORIENTED_EDGE('',*,*,#1244,.T.);
#1246=CARTESIAN_POINT('',(-24.9191403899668,-4.19496483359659,13.4109144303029));
#1247=CARTESIAN_POINT('',(-23.8381391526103,-4.12417220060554,12.8535823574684));
#1248=CARTESIAN_POINT('',(-22.7428134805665,-4.05244148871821,12.3242059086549));
#1249=CARTESIAN_POINT('',(-20.5293345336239,-3.90748513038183,11.3241128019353));
#1250=CARTESIAN_POINT('',(-19.4112500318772,-3.83426398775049,10.8532432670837));
#1251=CARTESIAN_POINT('',(-17.1522467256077,-3.68632632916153,9.96991193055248));
#1252=CARTESIAN_POINT('',(-16.0113274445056,-3.61160978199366,9.55745134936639));
#1253=CARTESIAN_POINT('',(-14.2836536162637,-3.49846784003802,8.98318373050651));
#1254=CARTESIAN_POINT('',(-13.7042390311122,-3.46052312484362,8.79894257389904));
#1255=CARTESIAN_POINT('',(-12.5407906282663,-3.38433119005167,8.44572577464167));
#1256=CARTESIAN_POINT('',(-11.9567567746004,-3.34608396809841,8.27675025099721));
#1257=CARTESIAN_POINT('',(-11.370572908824,-3.30769594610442,8.115508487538));
#1258=B_SPLINE_CURVE_WITH_KNOTS('',3,(#1246,#1247,#1248,#1249,#1250,#1251,#1252,#1253,#1254,
#1255,#1256,#1257),.UNSPECIFIED.,.F.,.F.,(4,2,2,2,2,4),(0.,3.65437061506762,7.29898215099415,
10.9436698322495,12.7710429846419,14.5984303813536),.UNSPECIFIED.);
#1259=EDGE_CURVE('E385',#316,#1243,#1258,.T.);
#1260=ORIENTED_EDGE('',*,*,#1259,.F.);
#1261=ORIENTED_EDGE('',*,*,#317,.F.);
#1262=EDGE_LOOP('',(#1183,#1214,#1218,#1245,#1260,#1261));
#1263=FACE_BOUND('',#1262,.T.);
#1264=ADVANCED_FACE('F217',(#1263),#401,.F.);
#1265=CARTESIAN_POINT('',(0.,0.,29.));
#1266=DIRECTION('',(0.,0.,1.));
#1267=DIRECTION('',(-1.09310760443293E-09,1.,0.));
#1268=AXIS2_PLACEMENT_3D('',#1265,#1266,#1267);
#1269=CYLINDRICAL_SURFACE('',#1268,9.5);
#1270=ORIENTED_EDGE('',*,*,#531,.T.);
#1271=EDGE_LOOP('',(#1270));
#1272=FACE_BOUND('',#1271,.T.);
#1273=ORIENTED_EDGE('',*,*,#1217,.F.);
#1274=DIRECTION('',(0.,0.,-1.));
#1275=VECTOR('',#1274,1.);
#1276=CARTESIAN_POINT('',(-8.07537698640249,5.00382718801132,63.));
#1277=LINE('',#1276,#1275);
#1278=EDGE_CURVE('E448',#666,#1212,#1277,.T.);
#1279=ORIENTED_EDGE('',*,*,#1278,.F.);
#1280=ORIENTED_EDGE('',*,*,#811,.F.);
#1281=DIRECTION('',(0.,0.,-1.));
#1282=VECTOR('',#1281,1.);
#1283=CARTESIAN_POINT('',(8.07537710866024,5.00382699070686,63.));
#1284=LINE('',#1283,#1282);
#1285=EDGE_CURVE('E445',#803,#410,#1284,.T.);
#1286=ORIENTED_EDGE('',*,*,#1285,.T.);
#1287=ORIENTED_EDGE('',*,*,#411,.F.);
#1288=DIRECTION('',(0.,0.,-1.));
#1289=VECTOR('',#1288,1.);
#1290=CARTESIAN_POINT('',(8.07537707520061,-5.00382704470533,63.));
#1291=LINE('',#1290,#1289);
#1292=EDGE_CURVE('E43',#719,#408,#1291,.T.);
#1293=ORIENTED_EDGE('',*,*,#1292,.F.);
#1294=ORIENTED_EDGE('',*,*,#720,.F.);
#1295=DIRECTION('',(0.,0.,-1.));
#1296=VECTOR('',#1295,1.);
#1297=CARTESIAN_POINT('',(-8.07537699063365,-5.00382718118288,63.));
#1298=LINE('',#1297,#1296);
#1299=EDGE_CURVE('E455',#710,#1216,#1298,.T.);
#1300=ORIENTED_EDGE('',*,*,#1299,.T.);
#1301=EDGE_LOOP('',(#1273,#1279,#1280,#1286,#1287,#1293,#1294,#1300));
#1302=FACE_BOUND('',#1301,.T.);
#1303=ADVANCED_FACE('F156',(#1272,#1302),#1269,.T.);
#1304=CARTESIAN_POINT('',(11.1355199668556,-6.9000141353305,63.));
#1305=DIRECTION('',(0.,0.,-1.));
#1306=DIRECTION('',(1.09310760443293E-09,-1.,0.));
#1307=AXIS2_PLACEMENT_3D('',#1304,#1305,#1306);
#1308=CYLINDRICAL_SURFACE('',#1307,3.6);
#1309=ORIENTED_EDGE('',*,*,#755,.T.);
#1310=ORIENTED_EDGE('',*,*,#1292,.T.);
#1311=ORIENTED_EDGE('',*,*,#503,.F.);
#1312=DIRECTION('',(0.,0.,-1.));
#1313=VECTOR('',#1312,1.);
#1314=CARTESIAN_POINT('',(11.3707729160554,-3.3077090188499,63.));
#1315=LINE('',#1314,#1313);
#1316=EDGE_CURVE('E147',#754,#473,#1315,.T.);
#1317=ORIENTED_EDGE('',*,*,#1316,.F.);
#1318=EDGE_LOOP('',(#1309,#1310,#1311,#1317));
#1319=FACE_BOUND('',#1318,.T.);
#1320=ADVANCED_FACE('F145',(#1319),#1308,.F.);
#1321=CARTESIAN_POINT('',(11.3707729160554,-3.3077090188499,63.));
#1322=DIRECTION('',(0.0653480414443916,0.997862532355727,0.));
#1323=DIRECTION('',(-0.997862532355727,0.0653480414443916,0.));
#1324=AXIS2_PLACEMENT_3D('',#1321,#1322,#1323);
#1325=PLANE('',#1324);
#1326=CARTESIAN_POINT('',(21.5941178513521,-3.97721563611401,22.4));
#1327=DIRECTION('',(-0.0653480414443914,-0.997862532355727,0.));
#1328=DIRECTION('',(0.997862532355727,-0.0653480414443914,0.));
#1329=AXIS2_PLACEMENT_3D('',#1326,#1327,#1328);
#1330=CIRCLE('',#1329,6.25599712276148);
#1331=CARTESIAN_POINT('',(27.836742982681,-4.38603279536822,22.4));
#1332=VERTEX_POINT('',#1331);
#1333=EDGE_CURVE('E574',#1332,#1332,#1330,.T.);
#1334=ORIENTED_EDGE('',*,*,#1333,.F.);
#1335=EDGE_LOOP('',(#1334));
#1336=FACE_BOUND('',#1335,.T.);
#1337=ORIENTED_EDGE('',*,*,#1316,.T.);
#1338=ORIENTED_EDGE('',*,*,#474,.T.);
#1339=ORIENTED_EDGE('',*,*,#1088,.T.);
#1340=DIRECTION('',(0.,0.,-1.));
#1341=VECTOR('',#1340,1.);
#1342=CARTESIAN_POINT('',(29.577018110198,-4.49999996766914,63.));
#1343=LINE('',#1342,#1341);
#1344=EDGE_CURVE('E431',#1012,#1066,#1343,.T.);
#1345=ORIENTED_EDGE('',*,*,#1344,.F.);
#1346=ORIENTED_EDGE('',*,*,#1013,.T.);
#1347=ORIENTED_EDGE('',*,*,#764,.F.);
#1348=EDGE_LOOP('',(#1337,#1338,#1339,#1345,#1346,#1347));
#1349=FACE_BOUND('',#1348,.T.);
#1350=ADVANCED_FACE('F220',(#1336,#1349),#1325,.F.);
#1351=CARTESIAN_POINT('',(-29.57701810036,-4.50000003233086,63.));
#1352=DIRECTION('',(-0.0653480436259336,0.997862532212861,0.));
#1353=DIRECTION('',(-0.997862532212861,-0.0653480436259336,0.));
#1354=AXIS2_PLACEMENT_3D('',#1351,#1352,#1353);
#1355=PLANE('',#1354);
#1356=CARTESIAN_POINT('',(-21.5941178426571,-3.9772156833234,22.4));
#1357=DIRECTION('',(-0.0653480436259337,0.997862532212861,0.));
#1358=DIRECTION('',(-0.997862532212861,-0.0653480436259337,0.));
#1359=AXIS2_PLACEMENT_3D('',#1356,#1357,#1358);
#1360=CIRCLE('',#1359,6.25599712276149);
#1361=CARTESIAN_POINT('',(-27.8367429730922,-4.38603285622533,22.4));
#1362=VERTEX_POINT('',#1361);
#1363=EDGE_CURVE('E163',#1362,#1362,#1360,.T.);
#1364=ORIENTED_EDGE('',*,*,#1363,.T.);
#1365=EDGE_LOOP('',(#1364));
#1366=FACE_BOUND('',#1365,.T.);
#1367=ORIENTED_EDGE('',*,*,#123,.T.);
#1368=DIRECTION('',(0.,0.,-1.));
#1369=VECTOR('',#1368,1.);
#1370=CARTESIAN_POINT('',(-29.5770181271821,-4.50000003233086,63.));
#1371=LINE('',#1370,#1369);
#1372=EDGE_CURVE('E415',#122,#339,#1371,.T.);
#1373=ORIENTED_EDGE('',*,*,#1372,.T.);
#1374=ORIENTED_EDGE('',*,*,#340,.T.);
#1375=ORIENTED_EDGE('',*,*,#1259,.T.);
#1376=DIRECTION('',(0.,0.,-1.));
#1377=VECTOR('',#1376,1.);
#1378=CARTESIAN_POINT('',(-11.370772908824,-3.30770904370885,63.));
#1379=LINE('',#1378,#1377);
#1380=EDGE_CURVE('E457',#683,#1243,#1379,.T.);
#1381=ORIENTED_EDGE('',*,*,#1380,.F.);
#1382=ORIENTED_EDGE('',*,*,#684,.F.);
#1383=EDGE_LOOP('',(#1367,#1373,#1374,#1375,#1381,#1382));
#1384=FACE_BOUND('',#1383,.T.);
#1385=ADVANCED_FACE('F225',(#1366,#1384),#1355,.F.);
#1386=CARTESIAN_POINT('',(-11.1355199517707,-6.90001415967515,63.));
#1387=DIRECTION('',(0.,0.,-1.));
#1388=DIRECTION('',(1.09310760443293E-09,-1.,0.));
#1389=AXIS2_PLACEMENT_3D('',#1386,#1387,#1388);
#1390=CYLINDRICAL_SURFACE('',#1389,3.6);
#1391=ORIENTED_EDGE('',*,*,#711,.T.);
#1392=ORIENTED_EDGE('',*,*,#1380,.T.);
#1393=ORIENTED_EDGE('',*,*,#1244,.F.);
#1394=ORIENTED_EDGE('',*,*,#1299,.F.);
#1395=EDGE_LOOP('',(#1391,#1392,#1393,#1394));
#1396=FACE_BOUND('',#1395,.T.);
#1397=ADVANCED_FACE('F540',(#1396),#1390,.F.);
#1398=CARTESIAN_POINT('',(29.5770181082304,-2.69999996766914,63.));
#1399=DIRECTION('',(0.,0.,-1.));
#1400=DIRECTION('',(1.09310760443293E-09,-1.,0.));
#1401=AXIS2_PLACEMENT_3D('',#1398,#1399,#1400);
#1402=CYLINDRICAL_SURFACE('',#1401,1.8);
#1403=ORIENTED_EDGE('',*,*,#1038,.T.);
#1404=ORIENTED_EDGE('',*,*,#1344,.T.);
#1405=ORIENTED_EDGE('',*,*,#1067,.T.);
#1406=EDGE_LOOP('',(#1403,#1404,#1405));
#1407=FACE_BOUND('',#1406,.T.);
#1408=ADVANCED_FACE('F227',(#1407),#1402,.T.);
#1409=CARTESIAN_POINT('',(-29.5770181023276,-2.70000003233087,63.));
#1410=DIRECTION('',(0.,0.,-1.));
#1411=DIRECTION('',(1.09310760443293E-09,-1.,0.));
#1412=AXIS2_PLACEMENT_3D('',#1409,#1410,#1411);
#1413=CYLINDRICAL_SURFACE('',#1412,1.8);
#1414=ORIENTED_EDGE('',*,*,#365,.T.);
#1415=ORIENTED_EDGE('',*,*,#1372,.F.);
#1416=ORIENTED_EDGE('',*,*,#392,.T.);
#1417=EDGE_LOOP('',(#1414,#1415,#1416));
#1418=FACE_BOUND('',#1417,.T.);
#1419=ADVANCED_FACE('F355',(#1418),#1413,.T.);
#1420=CARTESIAN_POINT('',(-11.3707729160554,3.3077090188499,63.));
#1421=DIRECTION('',(-0.0653480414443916,-0.997862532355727,0.));
#1422=DIRECTION('',(0.997862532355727,-0.0653480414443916,0.));
#1423=AXIS2_PLACEMENT_3D('',#1420,#1421,#1422);
#1424=PLANE('',#1423);
#1425=CARTESIAN_POINT('',(-21.5941178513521,3.97721563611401,22.4));
#1426=DIRECTION('',(0.0653480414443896,0.997862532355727,0.));
#1427=DIRECTION('',(-0.997862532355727,0.0653480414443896,0.));
#1428=AXIS2_PLACEMENT_3D('',#1425,#1426,#1427);
#1429=CIRCLE('',#1428,6.25599712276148);
#1430=CARTESIAN_POINT('',(-27.836742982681,4.3860327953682,22.4));
#1431=VERTEX_POINT('',#1430);
#1432=EDGE_CURVE('E577',#1431,#1431,#1429,.T.);
#1433=ORIENTED_EDGE('',*,*,#1432,.F.);
#1434=EDGE_LOOP('',(#1433));
#1435=FACE_BOUND('',#1434,.T.);
#1436=DIRECTION('',(0.,0.,-1.));
#1437=VECTOR('',#1436,1.);
#1438=CARTESIAN_POINT('',(-11.3707729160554,3.3077090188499,63.));
#1439=LINE('',#1438,#1437);
#1440=EDGE_CURVE('E416',#664,#1181,#1439,.T.);
#1441=ORIENTED_EDGE('',*,*,#1440,.T.);
#1442=ORIENTED_EDGE('',*,*,#1182,.T.);
#1443=ORIENTED_EDGE('',*,*,#308,.T.);
#1444=DIRECTION('',(0.,0.,-1.));
#1445=VECTOR('',#1444,1.);
#1446=CARTESIAN_POINT('',(-29.577018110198,4.49999996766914,63.));
#1447=LINE('',#1446,#1445);
#1448=EDGE_CURVE('E407',#230,#284,#1447,.T.);
#1449=ORIENTED_EDGE('',*,*,#1448,.F.);
#1450=ORIENTED_EDGE('',*,*,#231,.T.);
#1451=ORIENTED_EDGE('',*,*,#674,.F.);
#1452=EDGE_LOOP('',(#1441,#1442,#1443,#1449,#1450,#1451));
#1453=FACE_BOUND('',#1452,.T.);
#1454=ADVANCED_FACE('F358',(#1435,#1453),#1424,.F.);
#1455=CARTESIAN_POINT('',(29.57701810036,4.50000003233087,63.));
#1456=DIRECTION('',(0.0653480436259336,-0.997862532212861,0.));
#1457=DIRECTION('',(0.997862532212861,0.0653480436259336,0.));
#1458=AXIS2_PLACEMENT_3D('',#1455,#1456,#1457);
#1459=PLANE('',#1458);
#1460=CARTESIAN_POINT('',(21.5941178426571,3.9772156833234,22.4));
#1461=DIRECTION('',(0.0653480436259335,-0.997862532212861,0.));
#1462=DIRECTION('',(0.997862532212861,0.0653480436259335,0.));
#1463=AXIS2_PLACEMENT_3D('',#1460,#1461,#1462);
#1464=CIRCLE('',#1463,6.2559971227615);
#1465=CARTESIAN_POINT('',(27.8367429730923,4.38603285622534,22.4));
#1466=VERTEX_POINT('',#1465);
#1467=EDGE_CURVE('E569',#1466,#1466,#1464,.T.);
#1468=ORIENTED_EDGE('',*,*,#1467,.T.);
#1469=EDGE_LOOP('',(#1468));
#1470=FACE_BOUND('',#1469,.T.);
#1471=ORIENTED_EDGE('',*,*,#913,.T.);
#1472=DIRECTION('',(0.,0.,-1.));
#1473=VECTOR('',#1472,1.);
#1474=CARTESIAN_POINT('',(29.57701810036,4.50000003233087,63.));
#1475=LINE('',#1474,#1473);
#1476=EDGE_CURVE('E446',#912,#1111,#1475,.T.);
#1477=ORIENTED_EDGE('',*,*,#1476,.T.);
#1478=ORIENTED_EDGE('',*,*,#1112,.T.);
#1479=ORIENTED_EDGE('',*,*,#455,.T.);
#1480=DIRECTION('',(0.,0.,-1.));
#1481=VECTOR('',#1480,1.);
#1482=CARTESIAN_POINT('',(11.370772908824,3.30770904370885,63.));
#1483=LINE('',#1482,#1481);
#1484=EDGE_CURVE('E441',#776,#437,#1483,.T.);
#1485=ORIENTED_EDGE('',*,*,#1484,.F.);
#1486=ORIENTED_EDGE('',*,*,#777,.F.);
#1487=EDGE_LOOP('',(#1471,#1477,#1478,#1479,#1485,#1486));
#1488=FACE_BOUND('',#1487,.T.);
#1489=ADVANCED_FACE('F372',(#1470,#1488),#1459,.F.);
#1490=CARTESIAN_POINT('',(-11.1355199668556,6.90001413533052,63.));
#1491=DIRECTION('',(0.,0.,-1.));
#1492=DIRECTION('',(1.09310760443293E-09,-1.,0.));
#1493=AXIS2_PLACEMENT_3D('',#1490,#1491,#1492);
#1494=CYLINDRICAL_SURFACE('',#1493,3.6);
#1495=ORIENTED_EDGE('',*,*,#667,.T.);
#1496=ORIENTED_EDGE('',*,*,#1278,.T.);
#1497=ORIENTED_EDGE('',*,*,#1213,.F.);
#1498=ORIENTED_EDGE('',*,*,#1440,.F.);
#1499=EDGE_LOOP('',(#1495,#1496,#1497,#1498));
#1500=FACE_BOUND('',#1499,.T.);
#1501=ADVANCED_FACE('F374',(#1500),#1494,.F.);
#1502=CARTESIAN_POINT('',(11.1355199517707,6.90001415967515,63.));
#1503=DIRECTION('',(0.,0.,-1.));
#1504=DIRECTION('',(1.09310760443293E-09,-1.,0.));
#1505=AXIS2_PLACEMENT_3D('',#1502,#1503,#1504);
#1506=CYLINDRICAL_SURFACE('',#1505,3.6);
#1507=ORIENTED_EDGE('',*,*,#804,.T.);
#1508=ORIENTED_EDGE('',*,*,#1484,.T.);
#1509=ORIENTED_EDGE('',*,*,#438,.F.);
#1510=ORIENTED_EDGE('',*,*,#1285,.F.);
#1511=EDGE_LOOP('',(#1507,#1508,#1509,#1510));
#1512=FACE_BOUND('',#1511,.T.);
#1513=ADVANCED_FACE('F366',(#1512),#1506,.F.);
#1514=CARTESIAN_POINT('',(-29.5770181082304,2.69999996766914,63.));
#1515=DIRECTION('',(0.,0.,-1.));
#1516=DIRECTION('',(1.09310760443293E-09,-1.,0.));
#1517=AXIS2_PLACEMENT_3D('',#1514,#1515,#1516);
#1518=CYLINDRICAL_SURFACE('',#1517,1.8);
#1519=ORIENTED_EDGE('',*,*,#256,.T.);
#1520=ORIENTED_EDGE('',*,*,#1448,.T.);
#1521=ORIENTED_EDGE('',*,*,#285,.T.);
#1522=EDGE_LOOP('',(#1519,#1520,#1521));
#1523=FACE_BOUND('',#1522,.T.);
#1524=ADVANCED_FACE('F361',(#1523),#1518,.T.);
#1525=CARTESIAN_POINT('',(29.5770181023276,2.70000003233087,63.));
#1526=DIRECTION('',(0.,0.,-1.));
#1527=DIRECTION('',(1.09310760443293E-09,-1.,0.));
#1528=AXIS2_PLACEMENT_3D('',#1525,#1526,#1527);
#1529=CYLINDRICAL_SURFACE('',#1528,1.8);
#1530=ORIENTED_EDGE('',*,*,#1137,.T.);
#1531=ORIENTED_EDGE('',*,*,#1476,.F.);
#1532=ORIENTED_EDGE('',*,*,#1164,.T.);
#1533=EDGE_LOOP('',(#1530,#1531,#1532));
#1534=FACE_BOUND('',#1533,.T.);
#1535=ADVANCED_FACE('F365',(#1534),#1529,.T.);
#1536=CARTESIAN_POINT('',(-20.6909836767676,-17.7680454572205,22.4));
#1537=DIRECTION('',(-0.0653480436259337,0.997862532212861,0.));
#1538=DIRECTION('',(0.997862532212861,0.0653480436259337,0.));
#1539=AXIS2_PLACEMENT_3D('',#1536,#1537,#1538);
#1540=SPHERICAL_SURFACE('',#1539,15.1703703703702);
#1541=ORIENTED_EDGE('',*,*,#1363,.F.);
#1542=EDGE_LOOP('',(#1541));
#1543=FACE_BOUND('',#1542,.T.);
#1544=ADVANCED_FACE('F487',(#1543),#1540,.F.);
#1545=CARTESIAN_POINT('',(-20.6909837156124,17.7680454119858,22.4));
#1546=DIRECTION('',(0.0653480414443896,0.997862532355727,0.));
#1547=DIRECTION('',(-0.997862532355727,0.0653480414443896,0.));
#1548=AXIS2_PLACEMENT_3D('',#1545,#1546,#1547);
#1549=SPHERICAL_SURFACE('',#1548,15.1703703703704);
#1550=ORIENTED_EDGE('',*,*,#1432,.T.);
#1551=EDGE_LOOP('',(#1550));
#1552=FACE_BOUND('',#1551,.T.);
#1553=ADVANCED_FACE('F493',(#1552),#1549,.F.);
#1554=CARTESIAN_POINT('',(20.6909837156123,-17.7680454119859,22.4));
#1555=DIRECTION('',(-0.0653480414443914,-0.997862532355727,0.));
#1556=DIRECTION('',(0.997862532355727,-0.0653480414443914,0.));
#1557=AXIS2_PLACEMENT_3D('',#1554,#1555,#1556);
#1558=SPHERICAL_SURFACE('',#1557,15.1703703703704);
#1559=ORIENTED_EDGE('',*,*,#1333,.T.);
#1560=EDGE_LOOP('',(#1559));
#1561=FACE_BOUND('',#1560,.T.);
#1562=ADVANCED_FACE('F547',(#1561),#1558,.F.);
#1563=CARTESIAN_POINT('',(20.6909836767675,17.7680454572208,22.4));
#1564=DIRECTION('',(0.0653480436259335,-0.997862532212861,0.));
#1565=DIRECTION('',(0.997862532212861,0.0653480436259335,0.));
#1566=AXIS2_PLACEMENT_3D('',#1563,#1564,#1565);
#1567=SPHERICAL_SURFACE('',#1566,15.1703703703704);
#1568=ORIENTED_EDGE('',*,*,#1467,.F.);
#1569=EDGE_LOOP('',(#1568));
#1570=FACE_BOUND('',#1569,.T.);
#1571=ADVANCED_FACE('F551',(#1570),#1567,.F.);
#1572=CARTESIAN_POINT('',(0.,0.,32.5417962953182));
#1573=DIRECTION('',(0.,0.,-1.));
#1574=DIRECTION('',(1.09310760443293E-09,-1.,0.));
#1575=AXIS2_PLACEMENT_3D('',#1572,#1573,#1574);
#1576=CYLINDRICAL_SURFACE('',#1575,5.);
#1577=ORIENTED_EDGE('',*,*,#559,.T.);
#1578=EDGE_LOOP('',(#1577));
#1579=FACE_BOUND('',#1578,.T.);
#1580=ORIENTED_EDGE('',*,*,#520,.T.);
#1581=EDGE_LOOP('',(#1580));
#1582=FACE_BOUND('',#1581,.T.);
#1583=ADVANCED_FACE('F555',(#1579,#1582),#1576,.F.);
#1584=CLOSED_SHELL('',(#396,#507,#535,#563,#583,#603,#623,#815,#1168,#1264,#1303,#1320,#1350,
#1385,#1397,#1408,#1419,#1454,#1489,#1501,#1513,#1524,#1535,#1544,#1553,#1562,#1571,#1583));
#1585=MANIFOLD_SOLID_BREP('B1',#1584);
#1586=ADVANCED_BREP_SHAPE_REPRESENTATION('',(#18,#1585),#14);
#1587=SHAPE_DEFINITION_REPRESENTATION(#9,#1586);
ENDSEC;
END-ISO-10303-21;
